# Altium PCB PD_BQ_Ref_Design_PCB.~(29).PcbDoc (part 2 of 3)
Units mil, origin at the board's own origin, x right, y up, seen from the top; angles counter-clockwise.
Board outline 2000 x 3400 mil, 4 copper layers (Top Layer, Signal Layer 1, Signal Layer 2, Bottom Layer), stack 61.2 mil thick; 124 components, 53 nets, 359 pads, 494 vias.
Unrouted connection lines stored in the file: 227.

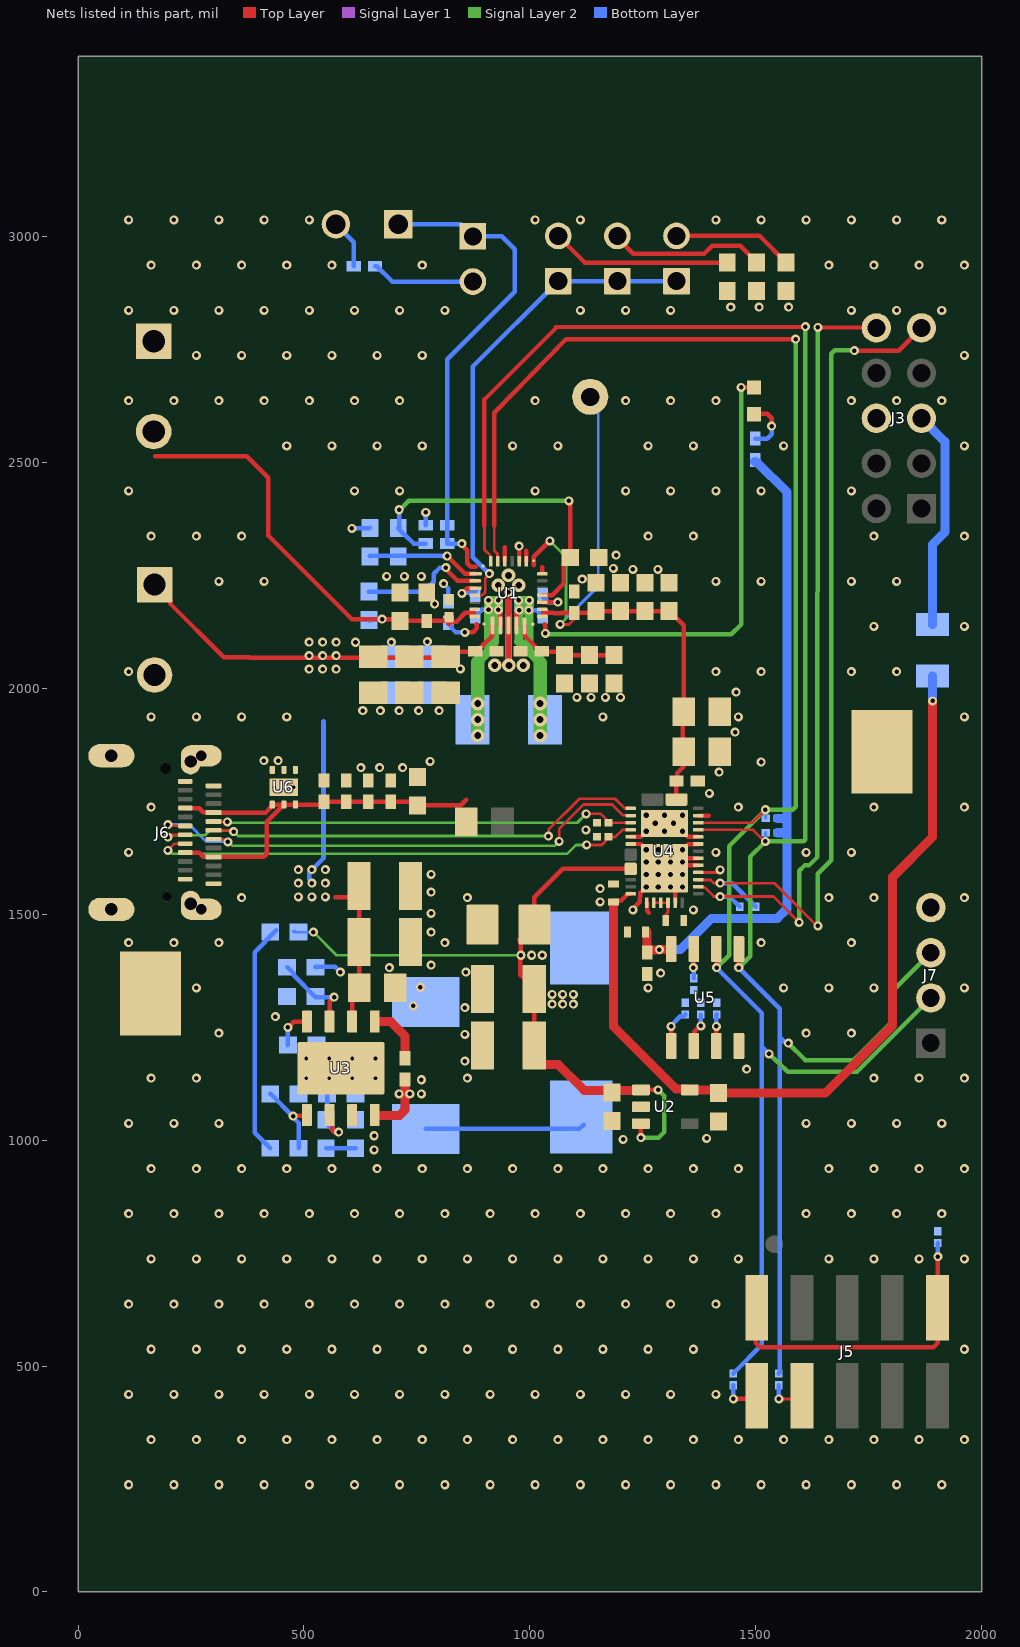
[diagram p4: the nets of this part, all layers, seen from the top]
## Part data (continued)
LOGO5: library part CMP-0074837-1, "IEC 61010-1 Hot Surface Warning"
NT1: library part CMP-0078142-3, "Single point connection between nets.", Manufacturer=N/A
R1: library part CMP-0022736-4, "RES, 100, 1%, 0.1 W, 0603", Manufacturer=Yageo, Power_W=100mW, Supplier Part Number 1=311-100HRCT-ND, TempCo="100 ppm/C", Tolerance_%=1%, Value2=0.1W, Value_Code=100R, ValueDisplayed=100
R2: library part CMP-0026232-2, "RES, 2.21 k, 1%, 0.063 W, AEC-Q200 Grade 0, 0402", Manufacturer=Vishay-Dale, Power_W=63mW, Supplier Part Number 1=541-2.21KLCT-ND, TempCo="100 ppm/C", Tolerance_%=1%, Value2=0.063W, Value_Code=2k21, ValueDisplayed=2.21k
R3: library part CMP-0026464-2, "RES, 5.23 k, 1%, 0.063 W, AEC-Q200 Grade 0, 0402", Manufacturer=Vishay-Dale, PartNumber=CRCW04025K23FKED, Power_W=63mW, Supplier Part Number 1=541-5.23KLCT-ND, TempCo="100 ppm/C", Tolerance_%=1%, Value2=0.063W, Value_Code=5k23, ValueDisplayed=5.23k
R4: library part CMP-0022788-4, "RES, 137 k, 1%, 0.1 W, 0603", Manufacturer=Yageo, Power_W=100mW, Supplier Part Number 1=311-137KHRCT-ND, TempCo="100 ppm/C", Tolerance_%=1%, Value2=0.1W, Value_Code=137k
R5: library part CMP-0026284-2, "RES, 30.1 k, 1%, 0.063 W, AEC-Q200 Grade 0, 0402", Manufacturer=Vishay-Dale, PartNumber=CRCW040230K1FKED, Power_W=63mW, Supplier Part Number 1=541-30.1KLCT-ND, TempCo="100 ppm/C", Tolerance_%=1%, Value2=0.063W, Value_Code=30k1, ValueDisplayed=30.1k
R6: library part CMP-0022735-5, "RES, 100 k, 1%, 0.1 W, 0603", Manufacturer=Yageo, Power_W=100mW, Supplier Part Number 1=311-100KHRCT-ND, TempCo="100 ppm/C", Tolerance_%=1%, Value2=0.1W, Value_Code=100k
R7: library part CMP-0025958-3, "RES, 10.0 k, 1%, 0.063 W, AEC-Q200 Grade 0, 0402", Manufacturer=Vishay-Dale, PartNumber=CRCW040210K0FKED, Power_W=63mW, Supplier Part Number 1=541-10.0KLCT-ND, TempCo="100 ppm/C", Tolerance_%=1%, Value2=0.063W, Value_Code=10k0, ValueDisplayed=10.0k
R8: library part CMP-0023246-5, "RES, 6.04 k, 1%, 0.1 W, 0603", Manufacturer=Yageo, Power_W=100mW, Supplier Part Number 1=311-6.04KHRCT-ND, TempCo="100 ppm/C", Tolerance_%=1%, Value2=0.1W, Value_Code=6k04, ValueDisplayed=6.04k
R9: library part CMP-0022000-4, "RES, 10.5 k, 1%, 0.1 W, AEC-Q200 Grade 0, 0603", Manufacturer=Vishay-Dale, Power_W=100mW, Supplier Part Number 1=541-10.5KHCT-ND, TempCo="100 ppm/C", Tolerance_%=1%, Value2=0.1W, Value_Code=10k5, ValueDisplayed=10.5k
R10: library part CMP-0022089-4, "RES, 17.4 k, 1%, 0.1 W, AEC-Q200 Grade 0, 0603", Manufacturer=Vishay-Dale, Power_W=100mW, Supplier Part Number 1=541-17.4KHCT-ND, TempCo="100 ppm/C", Tolerance_%=1%, Value2=0.1W, Value_Code=17k4, ValueDisplayed=17.4k
R11: library part CMP-0017299-3, "RES, 10.0, 1%, 0.25 W, AEC-Q200 Grade 0, 1206", Manufacturer=Panasonic, Power_W=250mW, Supplier Part Number 1=P10.0FCT-ND, TempCo="100 ppm/C", Tolerance_%=1%, Value2=0.25W, Value_Code=10R0, ValueDisplayed=10.0
R12: library part CMP-0022483-4, "RES, 51.1, 1%, 0.1 W, AEC-Q200 Grade 0, 0603", Manufacturer=Vishay-Dale, Power_W=100mW, Supplier Part Number 1=541-51.1HCT-ND, TempCo="100 ppm/C", Tolerance_%=1%, Value2=0.1W, Value_Code=51R1, ValueDisplayed=51.1
R13: library part CMP-0022546-4, "RES, 665 k, 1%, 0.1 W, AEC-Q200 Grade 0, 0603", Manufacturer=Vishay-Dale, Power_W=100mW, Supplier Part Number 1=541-665KHCT-ND, TempCo="100 ppm/C", Tolerance_%=1%, Value2=0.1W, Value_Code=665k
R14: library part CMP-0021999-4, "RES, 10.2 k, 1%, 0.1 W, AEC-Q200 Grade 0, 0603", Manufacturer=Vishay-Dale, Power_W=100mW, Supplier Part Number 1=541-10.2KHCT-ND, TempCo="100 ppm/C", Tolerance_%=1%, Value2=0.1W, Value_Code=10k2, ValueDisplayed=10.2k
R15: library part CMP-0022036-4, "RES, 130 k, 1%, 0.1 W, AEC-Q200 Grade 0, 0603", Manufacturer=Vishay-Dale, Power_W=100mW, Supplier Part Number 1=541-130KHCT-ND, TempCo="100 ppm/C", Tolerance_%=1%, Value2=0.1W, Value_Code=130k
R16: library part CMP-0022137-4, "RES, 1.96 k, 1%, 0.1 W, AEC-Q200 Grade 0, 0603", Manufacturer=Vishay-Dale, Power_W=100mW, Supplier Part Number 1=541-1.96KHCT-ND, TempCo="100 ppm/C", Tolerance_%=1%, Value2=0.1W, Value_Code=1k96, ValueDisplayed=1.96k
R17: library part CMP-0022360-4, "RES, 37.4 k, 1%, 0.1 W, AEC-Q200 Grade 0, 0603", Manufacturer=Vishay-Dale, Power_W=100mW, Supplier Part Number 1=541-37.4KHCT-ND, TempCo="100 ppm/C", Tolerance_%=1%, Value2=0.1W, Value_Code=37k4, ValueDisplayed=37.4k
R21 R22 R24 R25: library part CMP-0027272-3, "RES, 2.20 k, 1%, 0.05 W, 0201", Manufacturer=Vishay-Dale, Power_W=50mW, Supplier Part Number 1=541-2.20KAABCT-ND, TempCo="100 ppm/C", Tolerance_%=1%, Value2=0.05W, Value_Code=2k20, ValueDisplayed=2.20k
R26 R27 R29: library part CMP-0027008-4, "RES, 0, 5%, 0.05 W, 0201", Manufacturer=Vishay-Dale, Power_W=50mW, Supplier Part Number 1=72M6743, TempCo=ppm/C, Tolerance_%=5%, Value2=0.05W, Value_Code=0000, ValueDisplayed=0
R28 R30 R31 R32: library part CMP-0027262-3, "RES, 10.0 k, 1%, 0.05 W, 0201", Manufacturer=Vishay-Dale, Power_W=50mW, Supplier Part Number 1=541-10.0KAABCT-ND, TempCo="100 ppm/C", Tolerance_%=1%, Value2=0.05W, Value_Code=10k0, ValueDisplayed=10.0k
SH-J1 SH-J2: library part CMP-0003623-1, "Shunt, 100mil, Gold plated, Black", Alternate Manufacturer=3M, Alternate PartNumber=969102-0000-DA, Manufacturer=Samtec, Supplier Part Number 1=SNT-100-BK-G-ND
TP1: library part CMP-0055137-1, "Test Point, Miniature, Red, TH", Color=Red, Manufacturer=Keystone, Supplier Part Number 1=36-5000-ND
TP2 TP3: library part CMP-0055153-1, "Test Point, Compact, SMT", Manufacturer=Keystone, Supplier Part Number 1=36-5016TR-ND
U1: library part CMP-0088656-1, "BQ2579x HotRod", Manufacturer="Texas Instruments", Operating Temperature Range=to
U2: library part CMP-0074640-3, "500-mA, Low IQ, Small Size, Low Dropout Regulator, DBV0005A (SOT-23-5)", Alternate Manufacturer="Texas Instruments"
U3: library part CMP-0067056-2, "3.5V to 28V Input, 5A, 570kHz Step-Down Converter with Eco-mode, DDA0008E (SOIC-8)", Alternate Manufacturer="Texas Instruments", Alternate PartNumber=TPS54531DDA
U4: library part CMP-0090338-5, "USB Type-C and USB PD Controller with Integrated Power Switches Optimized for Power Applications", Manufacturer="Texas Instruments", Max Supply Voltage=22V, Min Supply Voltage=3V, Operating Temperature Range="-40°C to +125°C"
U5: library part CMP-0005314-2, "256 kb I2C CMOS Serial EEPROM, SOIC-8", Manufacturer="ON Semiconductor", Supplier Part Number 1=CAT24C256WI-G-ND
U6: library part CMP-0077834-1, "22-V Precision Surge Protection Clamp, DRV0006A (WSON-6)", Alternate Manufacturer="Texas Instruments"
ZZ1: library part CMP-0003616-3

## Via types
v1: diameter 20, hole 10, Top Layer to Bottom Layer, tented both sides, 445 vias
v2: diameter 23.62, hole 11.81, Top Layer to Bottom Layer, 24 vias
v3: diameter 30, hole 15, Top Layer to Bottom Layer, tented both sides, 12 vias
v4: diameter 19.68, hole 7.87, Top Layer to Bottom Layer, tented both sides, 10 vias
v5: diameter 20, hole 10, Top Layer to Bottom Layer, 3 vias

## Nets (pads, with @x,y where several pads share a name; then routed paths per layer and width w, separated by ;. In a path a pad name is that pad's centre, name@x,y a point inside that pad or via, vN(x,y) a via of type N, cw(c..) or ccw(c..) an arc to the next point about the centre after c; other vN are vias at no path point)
AGND: C22.2 J3.6 J4.2 NT1.2 R5.1 R6.1 R7.1 R8.1 R9.1 R10.1 U1.10 U1.11 U1.13 | length 298.5
  Top Layer w10: 944.88,2312.99 945,2312.87 U1.13@945,2281.4 ; 976.38,2303.15 976.38,2281.51 U1.11@976.5,2281.4 ; 992.13,2305.12 992.24,2305 U1.10@992.24,2281.4
  Bottom Layer w10: J4.2@570.87,3027.56 610.24,2988.19 R7.1@610.24,2935.04 ; v1(606.3,2354.33) 644.87,2354.33 R6.1@645.85,2355.32 ; v1(769.69,2389.76) 769.69,2361.34 R5.1@769.8,2361.22 ; v1(809.06,2232.28) 820,2221.34 C22.2@820,2192.91
  other v1: 976.38,2314.96 1444.88,2844.49 1507.87,2844.49 1572.83,2844.49
BAT: C19.1 C20.1 C21.1 J2.2 R1.1 U1.22 U1.23 | length 977.6
  Top Layer w10: 171.26,2514.17 373.62,2514.17 421.26,2466.54 421.26,2338.58 606.3,2153.54 v1(672.86,2153.54) 708.78,2153.54 C21.1@712.72,2149.61 C20.1@771.77,2149.61 815.08,2149.61 820.98,2143.7 ; 820.98,2141.73 820.98,2143.7 ; 877.09,2167.32 857.4,2167.32 837.83,2147.75 825.04,2147.75 820.98,2143.7
  Bottom Layer w10: R1.1@643.7,2151.57 645.67,2149.61 649.61,2153.54 v1(672.86,2153.54)
C_CC1: C42.1 J6.A5 U4.28 | length 942.2
  Top Layer w6: J6.A5@300.2,1705.71 300.69,1705.22 330.22,1705.22 v1(330.71,1704.72) ; v1(1124.81,1722.44) 1157.38,1722.44 1174.41,1705.41 C42.1@1174.41,1702.76 1223.06,1702.76 U4.28@1223.24,1702.94
  Signal Layer 2 w6: v1(330.71,1704.72) 332.68,1702.76 1105.12,1702.76 v1(1124.81,1722.44)
C_CC2: C41.1 J6.B5 U4.29 | length 1095.8
  Top Layer w6: v1(198.82,1641.73) 213.58,1656.5 J6.B5@237.2,1656.5 ; v1(1125.98,1653.54) 1159.35,1653.54 1174.41,1668.61 C41.1@1174.41,1671.26 1188.98,1671.26 1204.91,1687.19 U4.29@1223.24,1687.19
  Signal Layer 2 w6: v1(198.82,1641.73) 201.46,1641.73 209.33,1633.86 1082.68,1633.86 1102.36,1653.54 v1(1125.98,1653.54)
C_USB_N: J6.A7 J6.B7 U4.27 | length 1182
  Top Layer w6: v1(198.82,1698.82) 201.77,1695.87 J6.B7@237.2,1695.87 ; J6.A7@300.2,1666.34 325.79,1666.34 v1(331.63,1660.49) ; v1(1064.96,1661.42) 1064.96,1688.98 1118.92,1742.94 1182.26,1742.94 1205.57,1719.62 1222.3,1719.62 U4.27@1223.24,1718.68
  Signal Layer 2 w6: v1(331.63,1660.49) 333.23,1660.49 342.15,1651.57 1054.45,1651.57 v1@1064.62,1661.75
  Bottom Layer w6: v1(198.82,1698.82) 246.06,1698.82 284.39,1660.49 v1(331.63,1660.49) ; v1@1064.29,1661.42 v1(1064.96,1661.42)
C_USB_P: J6.A6 J6.B6 U4.26 | length 1175.4
  Top Layer w6: v1(198.82,1670.82) 202.61,1670.82 207.97,1676.18 J6.B6@237.2,1676.18 ; J6.A6@300.2,1686.02 337.75,1686.02 340.7,1683.07 v1(344.49,1683.07) ; v1(1041.34,1673.23) 1041.88,1673.77 1041.88,1687.55 1110.24,1755.91 1188.98,1755.91 1209.51,1735.37 1222.3,1735.37 U4.26@1223.24,1734.43
  Signal Layer 2 w6: v1(198.82,1670.82) 202.61,1670.82 206.99,1675.2 281.5,1675.2 292.32,1686.02 333.97,1686.02 334.25,1685.75 341.81,1685.75 v1(344.49,1683.07) ; v1@343.01,1684.55 354.33,1673.23 v1(1041.34,1673.23)
GND: C2.1 C3.1 C4.1 C5.1 C6.2 C8.1 C9.1 C10.1 C11.2 C12.2 C13.2 C14.2 C15.2 C16.2 C17.2 C18.2 C19.2 C20.2 C21.2 C23.1 C24.1 C26.2 C27.2 C28.2 C29.2 C30.2 C31.2 C33.2 C34.2 C35.2 C36.2 C37.2 C38.2 C39.2 C40.2 C41.2 C42.2 C43.2 C44.2 C45.1 C46.1 C47.1 C48.1 D2.2 J1.2 J2.1 J6.A1 J6.A12 J6.B1 J6.B12 J6.S1 J6.S2 J6.S3 J6.S4 J7.4 NT1.1 R15.1 R16.1 R17.1 R28.1 R29.1 R30.1 R31.1 R32.1 TP2.1 TP3.1 U1.27 U2.2 U3.7 U3.9@581.69,1159.17 U4.5 U4.10 U4.11 U4.12 U4.14 U4.18 U4.31 U4.39 U5.4 U6.1 U6.2 U6.3 U6.7@455.71,1781.5 | length 894.8
  Top Layer w6: U4.10@1372.84,1592.7 1415.54,1592.7 v1(1421.26,1598.43)
  Top Layer w8: U4.31@1223.24,1655.69 1245.68,1655.69
  Top Layer w10: 952.87,2167.32 U1.27@952.87,2139.66 952.87,2051.18 v3(953.86,2051.18) ; v1(1228.35,1509.84) 1228.35,1512.55 1243.67,1527.87 1243.67,1537.15 1245.05,1538.53 1245.05,1547.58 1298.04,1600.57 U4.39@1298.04,1601.95 ; 1245.68,1655.69 U4.39@1298.04,1603.33 ; U4.39@1311.62,1588.37 U4.39@1298.04,1601.95 ; U4.39@1311.62,1615.54 U4.39@1298.04,1601.95 ; U4.39@1319.59,1624.89 1350.4,1655.69 U4.14@1372.84,1655.69 ; U4.39@1320.28,1624.2 U4.12@1372.84,1624.2 U4.39@1338.2,1624.2 ; U4.5@1321.66,1525.77 U4.39@1321.66,1578.33 ; U4.39@1338.2,1608.45 U4.11@1372.84,1608.45 ; U4.18@1372.84,1718.68 1395.85,1718.68
  Top Layer w15: 952.87,2167.32 v1@952.87,2212.79
  Signal Layer 1 w15: v1(952.87,2212.81) 952.99,2212.69 952.99,2052.05 v3(953.86,2051.18)
  other v1: 111.94,237.26 211.94,237.26 311.94,237.26 411.94,237.26 511.94,237.26 611.94,237.26 711.94,237.26 811.94,237.26 911.94,237.26 1011.94,237.26 1111.94,237.26 1211.94,237.26 1311.94,237.26 1411.94,237.26 1511.94,237.26 1611.94,237.26 1711.94,237.26 1811.94,237.26 1911.94,237.26 161.94,337.26 261.94,337.26 361.94,337.26 461.94,337.26 561.94,337.26 661.94,337.26 761.94,337.26 861.94,337.26 961.94,337.26 1061.94,337.26 1161.94,337.26 1261.94,337.26 1361.94,337.26 1461.94,337.26 1561.94,337.26 1661.94,337.26 1761.94,337.26 1861.94,337.26 1961.94,337.26 111.94,437.26 211.94,437.26 311.94,437.26 411.94,437.26 511.94,437.26 611.94,437.26 711.94,437.26 811.94,437.26 911.94,437.26 1011.94,437.26 1111.94,437.26 1211.94,437.26 1311.94,437.26 1411.94,437.26 161.94,537.26 261.94,537.26 361.94,537.26 461.94,537.26 561.94,537.26 661.94,537.26 761.94,537.26 861.94,537.26 961.94,537.26 1061.94,537.26 1161.94,537.26 1261.94,537.26 1361.94,537.26 1961.94,537.26 111.94,637.26 211.94,637.26 311.94,637.26 411.94,637.26 511.94,637.26 611.94,637.26 711.94,637.26 811.94,637.26 911.94,637.26 1011.94,637.26 1111.94,637.26 1211.94,637.26 1311.94,637.26 1411.94,637.26 161.94,737.26 261.94,737.26 361.94,737.26 461.94,737.26 561.94,737.26 661.94,737.26 761.94,737.26 861.94,737.26 961.94,737.26 1061.94,737.26 1161.94,737.26 1261.94,737.26 1361.94,737.26 1461.94,737.26 1661.94,737.26 1761.94,737.26 1861.94,737.26 1961.94,737.26 111.94,837.26 211.94,837.26 311.94,837.26 411.94,837.26 511.94,837.26 611.94,837.26 711.94,837.26 811.94,837.26 911.94,837.26 1011.94,837.26 1111.94,837.26 1211.94,837.26 1311.94,837.26 1411.94,837.26 1611.94,837.26 1711.94,837.26 1811.94,837.26 1911.94,837.26 161.94,937.26 261.94,937.26 361.94,937.26 461.94,937.26 561.94,937.26 661.94,937.26 761.94,937.26 861.94,937.26 961.94,937.26 1061.94,937.26 1161.94,937.26 1261.94,937.26 1361.94,937.26 1461.94,937.26 1661.94,937.26 1761.94,937.26 1861.94,937.26 1961.94,937.26 655.51,978.35 1206.69,1001.97 1391.42,1003.94 655.51,1009.84 111.94,1037.26 211.94,1037.26 311.94,1037.26 1611.94,1037.26 1711.94,1037.26 1811.94,1037.26 1911.94,1037.26 161.94,1137.26 261.94,1137.26 861.94,1137.26 1761.94,1137.26 1861.94,1137.26 1961.94,1137.26 1480,1157.48 856.3,1175.2 856.3,1234.25 311.94,1237.26 1611.94,1237.26 1711.94,1237.26 437.01,1273.62 856.3,1293.31 742.13,1297.24 261.94,1337.26 1261.94,1337.26 1561.94,1337.26 1661.94,1337.26 1761.94,1337.26 1961.94,1337.26 757.87,1338.58 1289.37,1370.08 858.27,1372.05 688.98,1381.89 781.5,1387.8 111.94,1437.26 211.94,1437.26 311.94,1437.26 811.94,1437.26 1511.94,1437.26 1711.94,1437.26 781.5,1460.63 781.5,1501.97 1362.2,1509.84 1155.51,1527.56 361.94,1537.26 861.94,1537.26 1661.94,1537.26 1761.94,1537.26 1961.94,1537.26 781.5,1549.21 1155.51,1557.09 781.5,1588.58 111.94,1637.26 1411.94,1637.26 1611.94,1637.26 1711.94,1637.26 1124.02,1687.01 161.94,1737.26 1461.94,1737.26 1761.94,1737.26 1961.94,1737.26 1397.64,1767.72 1419.29,1814.96 625.98,1824.8 667.32,1824.8 718.5,1824.8 1511.94,1837.26 779.53,1838.58 411.42,1840.55 442.91,1840.55 1454.72,1903.54 161.94,1937.26 261.94,1937.26 361.94,1937.26 461.94,1937.26 1161.94,1937.26 1461.94,1937.26 1961.94,1937.26 630.2,1950.78 669.29,1950.79 710.63,1950.79 753.94,1950.79 799.21,1950.79 1104.33,1980.32 1135.83,1980.32 1167.32,1980.32 1200.79,1980.32 1456.69,1992.13 111.94,2037.26 1411.94,2037.26 1511.94,2037.26 1711.94,2037.26 1811.94,2037.26 1761.94,2137.26 1961.94,2137.26 789.37,2187.01 311.94,2237.26 411.94,2237.26 1411.94,2237.26 1511.94,2237.26 1711.94,2237.26 1811.94,2237.26 1116.14,2242.13 683.07,2248.03 722.44,2248.03 759.84,2248.03 1228.35,2263.78 1283.46,2263.78 1185.04,2265.75 1190.94,2295.28 161.94,2337.26 261.94,2337.26 361.94,2337.26 1261.94,2337.26 1361.94,2337.26 1761.94,2337.26 1961.94,2337.26 111.94,2437.26 611.94,2437.26 711.94,2437.26 1011.94,2437.26 1211.94,2437.26 1311.94,2437.26 1411.94,2437.26 1511.94,2437.26 1711.94,2437.26 461.94,2537.26 561.94,2537.26 661.94,2537.26 761.94,2537.26 961.94,2537.26 1061.94,2537.26 1261.94,2537.26 1361.94,2537.26 1561.94,2537.26 1961.94,2537.26 111.94,2637.26 211.94,2637.26 311.94,2637.26 411.94,2637.26 511.94,2637.26 611.94,2637.26 711.94,2637.26 1011.94,2637.26 1211.94,2637.26 1311.94,2637.26 1411.94,2637.26 1711.94,2637.26 1811.94,2637.26 1911.94,2637.26 261.94,2737.26 361.94,2737.26 461.94,2737.26 561.94,2737.26 661.94,2737.26 761.94,2737.26 1961.94,2737.26 111.94,2837.26 211.94,2837.26 311.94,2837.26 411.94,2837.26 511.94,2837.26 611.94,2837.26 711.94,2837.26 811.94,2837.26 1111.94,2837.26 1211.94,2837.26 1311.94,2837.26 1711.94,2837.26 1811.94,2837.26 1911.94,2837.26 161.94,2937.26 261.94,2937.26 361.94,2937.26 461.94,2937.26 561.94,2937.26 761.94,2937.26 1661.94,2937.26 1761.94,2937.26 1861.94,2937.26 1961.94,2937.26 111.94,3037.26 211.94,3037.26 311.94,3037.26 411.94,3037.26 511.94,3037.26 1011.94,3037.26 1111.94,3037.26 1411.94,3037.26 1511.94,3037.26 1611.94,3037.26 1711.94,3037.26 1811.94,3037.26 1911.94,3037.26
  other v2: 1257.88,1560.61 1284.65,1560.61 1311.43,1560.61 1338.2,1560.61 1257.88,1588.17 1284.65,1588.17 1311.43,1588.17 1338.2,1588.17 1257.88,1615.73 1284.65,1615.73 1311.43,1615.73 1338.2,1615.73 1257.88,1643.29 1284.65,1643.29 1311.43,1643.29 1338.2,1643.29
  other v3: 922.36,2051.18 985.35,2051.18 930.22,2228.33 975.51,2228.35 952.86,2250.2
  other v4: 504.92,1137.52 556.1,1137.52 607.28,1137.52 658.46,1137.52 504.92,1180.83 556.1,1180.83 607.28,1180.83 658.46,1180.83 434.06,1781.5 477.36,1781.5
I2C1_SCL: J3.9 R21.1 U4.9 | length 1911.4
  Top Layer w6: U4.9@1372.84,1576.95 1373.78,1576.02 1400.47,1576.02 1407.59,1568.9 v1(1421.26,1568.9) 1541.34,1568.9 1636.81,1473.43 v5@1637.8,1472.44
  Top Layer w10: v5(1718.5,2748.03) 1816.93,2748.03 J3.9@1867.13,2798.23
  Signal Layer 2 w10: v5(1637.8,1474.41) 1637.8,1590.14 1667.32,1619.67 1667.32,2740.91 1675.2,2748.78 1717.76,2748.78 v5(1718.5,2748.03)
  Bottom Layer w10: v1(1421.26,1568.9) 1448.03,1568.9 R21.1@1500,1516.93
I2C1_SDA: J3.10 R22.1 U4.8 | length 1783.2
  Top Layer w6: U4.8@1372.84,1561.2 1373.78,1560.27 1386.58,1560.27 1407.48,1539.37 v1(1421.26,1539.37) 1539.37,1539.37 v1(1596.46,1482.28) v1@1596.46,1480.32
  Top Layer w10: v5(1637.8,2799.21) J3.10@1767.13,2798.23
  Signal Layer 2 w10: v1(1596.46,1482.28) 1596.46,1596.46 1608.27,1608.27 1618.11,1608.27 1635.83,1625.98 1637.8,2801.18 v5(1637.8,2799.21)
  Bottom Layer w10: v1(1421.26,1539.37) 1442.13,1539.37 R22.1@1464.57,1516.93
I2C_SCL: J7.2 R24.2 R26.1 U1.14 U4.17 U5.6 | length 4218
  Top Layer w6: 921.26,2360.24 921.26,2305.12 928.31,2298.06 928.31,2282.33 U1.14@929.25,2281.4 ; U4.17@1372.84,1702.94 1493.06,1702.94 v1(1521.65,1731.53)
  Top Layer w10: 921.26,2360.24 921.26,2610.24 1080.71,2773.62 v1(1588.58,2773.62) ; v1(1413.39,1381.89) U5.6@1413.39,1422.76
  Signal Layer 2 w10: v1(1413.39,1381.89) 1441.26,1409.76 1441.26,1651.14 v1(1521.65,1731.53) 1581.93,1731.53 1588.58,1738.19 v1(1588.58,2773.62) ; v1(1529.53,1190.94) 1570.87,1151.57 1724.41,1151.57 J7.2@1887.8,1314.96
  Bottom Layer w6: v1(1521.65,1731.53) 1521.65,1713.39 R24.2@1522.44,1712.6
  Bottom Layer w10: v1(1413.39,1381.89) 1513.78,1281.5 1513.78,1204.72 ; R26.1@1450.79,483.46 1450.79,484.25 1454.06,487.52 1454.14,487.52 1513.78,547.16 1513.78,1204.72 ; v1(1529.53,1190.94) 1515.75,1204.72 1513.78,1204.72
I2C_SDA: J7.3 R25.2 R27.1 U1.15 U4.16 U5.5 | length 4321.3
  Top Layer w6: 899.61,2360.24 899.61,2307.09 912.57,2294.13 912.57,2282.33 U1.15@913.5,2281.4 ; U4.16@1372.84,1687.19 1493.91,1687.19 1519.69,1661.42 v1(1521.65,1661.42)
  Top Layer w10: 899.61,2360.24 899.61,2639.76 1059.06,2799.21 ; 1057.09,2799.21 v1@1608.27,2801.18 ; v1(1462.6,1381.89) U5.5@1462.6,1422.76
  Signal Layer 2 w10: v1(1462.6,1381.89) 1488.19,1407.48 1488.19,1627.95 v1(1521.65,1661.42) 1606.3,1661.42 1610.24,1665.35 v1(1610.24,2801.18) ; v1(1572.44,1214.96) 1610.24,1177.17 1716.54,1177.17 1801.18,1261.81 1801.18,1328.35 J7.3@1887.8,1414.96
  Bottom Layer w6: v1(1521.65,1661.42) 1521.65,1680.31 R25.2@1522.44,1681.1
  Bottom Layer w10: v1(1462.6,1381.89) 1553.15,1291.34 1553.15,1228.35 ; R27.1@1551.18,483.46 1553.15,485.43 1553.15,1228.35 ; v1(1572.44,1214.96) 1566.54,1214.96 1553.15,1228.35
ILIM_HIZ: R4.1 R6.2 U1.17 | length 250.9
  Top Layer w10: v1(816.93,2293.3) 856.39,2253.84 U1.17@880.04,2253.84
  Bottom Layer w10: R6.2@645.85,2292.32 646.84,2293.31 806.61,2293.31 v1(816.93,2293.3)
LDO_1V5: C37.1 U4.2 U4.3 U4.4 | length 83
  Top Layer w6: U4.2@1274.42,1525.77 U4.3@1290.17,1525.77 U4.4@1305.91,1525.77 1305.91,1504.73 1301.18,1500 1301.18,1476.69 C37.1@1300.87,1476.38
LDO_3V3: C36.1 C43.1 R2.2 R21.2 R22.2 R24.1 R25.1 U4.1 U5.8 | length 1507.2
  Top Layer w10: U4.1@1258.67,1525.77 1259.73,1524.71 1259.73,1507.98 1263.78,1503.94
  Top Layer w20: C43.1@1259.84,1415.35 1259.84,1419.29 C43.1@1261.65,1421.1 ; C36.1@1259.84,1461.46 1259.84,1421.1 C43.1@1261.65,1421.1 ; U5.8@1312.99,1423.15 1311.73,1421.89 v1(1286.7,1421.89) 1286.07,1421.26 1273.37,1421.26 1273.21,1421.1 C43.1@1261.65,1421.1
  Bottom Layer w20: v1@1287.4,1421.89 1333.31,1421.89 1402.36,1490.95 1472.44,1490.95 1501.97,1490.95 1531.5,1490.95 1548.03,1490.95 1568.9,1511.81 1568.9,1680.61 ; R2.2@1498.03,2502.95 1500.83,2500.16 1503.78,2500.16 1568.9,2435.04 1568.9,1713.17 ; R25.1@1548.43,1681.1 1548.92,1680.61 1568.9,1680.61 ; R24.1@1548.43,1712.6 1568.32,1712.6 1568.9,1713.17 ; 1568.9,1680.61 1568.9,1713.17
NetC1_1: C1.1 U1.4 | length 76.9
  Top Layer w10: U1.4@1027.68,2190.84 1062.03,2190.84 v1(1062.13,2190.95)
  Bottom Layer w10: C1.1@1028.66,2206.69 1028.66,2202.76 1040.57,2190.84 1062.03,2190.84 v1(1062.13,2190.95)
NetC1_2: C1.2 L1.1 U1.28 | length 640.5
  Top Layer w10: U1.28@970.59,2139.66 971.65,2140.73 971.65,2168.5 v1(976.38,2173.23)
  Signal Layer 2 w20: 1022.76,2057.09 998.36,2081.48 ; v1(976.38,2173.23) 976.38,2194.02 v1(975.51,2194.88) v1(999.13,2194.88) 998.03,2193.78 v1(998.03,2173.23) ; v1(976.38,2173.23) v1(998.03,2173.23) ; v1(976.38,2173.23) 976.38,2105.23 975.49,2104.35 998.36,2081.48 ; v1(998.03,2173.23) 998.36,2172.9 998.36,2081.48
  Signal Layer 2 w30: v3(1022.76,1895.67) 1022.76,2057.09
  Bottom Layer w10: v1(998.03,2173.23) 1014.88,2173.23 C1.2@1028.66,2159.45
  Bottom Layer w20: v1@975.51,2175 976.38,2174.13 v1(976.38,2173.23) v1(998.03,2173.23) 998.03,2193.78 v1(999.13,2194.88) v1(975.51,2194.88) v1@975.51,2175
  other v3: 1022.76,1931.1 1022.76,1966.7
NetC7_1: C7.1 U1.19 | length 77
  Top Layer w10: v1(849.53,2210.63) 861.24,2222.34 U1.19@879.65,2222.34
  Bottom Layer w10: v1(849.53,2210.63) 851.03,2212.13 873.61,2212.13 C7.1@879.05,2206.69 ; C7.1@874.29,2210.63 C7.1@881.1,2217.44
NetC7_2: C7.2 L1.2 U1.26 | length 624.4
  Top Layer w10: v1(930.24,2173.8) 930.24,2172.49 934.09,2168.63 934.09,2140.73 U1.26@935.16,2139.66
  Signal Layer 2 w20: 884.96,2058.3 908.58,2081.93 v1(908.58,2174.62) 929.41,2174.62 v1(930.24,2173.8) ; 908.58,2088.58 922.36,2102.36 922.36,2165.92 v1(930.24,2173.8) ; v1@908.58,2175.61 v1(908.58,2194.88) v1(930.24,2194.88) v1(930.24,2173.8)
  Signal Layer 2 w30: v3(884.96,1895.67) v3(884.96,1931.1) v3(884.96,1966.56) 884.96,2058.3
  Bottom Layer w10: C7.2@879.05,2159.45 894.8,2175.2 895.38,2174.62 v1(908.58,2174.62)
  Bottom Layer w20: v1(908.58,2174.62) 929.41,2174.62 v1(930.24,2173.8) v1(930.24,2194.88) v1(908.58,2194.88) v1(908.58,2174.62)
NetC22_1: C22.1 U1.24 | length 87.7
  Top Layer w10: v1(856.3,2124.02) 856.95,2124.66 874.66,2124.66 882.84,2132.84 882.84,2140.78 881.89,2141.73
  Bottom Layer w10: C22.1@820,2145.67 826.81,2138.86 826.81,2133.81 836.61,2124.02 v1(856.3,2124.02)
NetC25_1: C25.1 U3.1 | length 129.4
  Top Layer w20: U3.1@656.69,1262.52 692.2,1262.52 723.68,1231.04 C25.1@723.68,1181.64
NetC25_2: C25.2 D2.1 L2.1 U3.8 | length 493.1
  Top Layer w20: U3.8@656.69,1055.83 656.81,1055.83 657.52,1055.12 711.96,1055.12 723.68,1066.83 C25.2@723.68,1134.4
  Bottom Layer w10: D2.1@769.69,1024.86 1109.51,1024.86 L2.1@1119.09,1034.45
  other v1: 710.63,1102.36 734.25,1102.36 759.84,1102.36 759.84,1133.86
NetC32_1: C32.1 C34.1 U3.6 | length 164.6
  Top Layer w10: U3.6@556.69,1055.83 562.52,1050 562.52,1022.13 566.93,1017.72 v1(576.77,1017.72)
  Bottom Layer w10: C32.1@550.72,1045.28 C32.1@550.72,1043.82 ; C34.1@551.18,1102.36 551.18,1047.24 C32.1@549.21,1045.28 C32.1@550.72,1043.82 ; C32.1@551.92,1035.66 553.44,1041.19 C32.1@550.72,1043.82 ; v1(576.77,1017.72) 569,1017.72 550.72,1036 C32.1@550.72,1043.82
NetC32_2: C32.2 R17.2 | length 65.9
  Bottom Layer w10: C32.2@549.21,982.28 R17.2@615.16,982.28
NetC33_1: C33.1 U3.4 | length 86.7
  Top Layer w10: v1(464.57,1250) 477.09,1262.52 U3.4@506.69,1262.52
  Bottom Layer w10: C33.1@464.57,1210.63 v1(464.57,1250)
NetC44_1: C44.1 C45.2 C46.2 C47.2 C48.2 J6.A4 J6.A9 J6.B4 J6.B9 L3.1 U6.4 U6.5 U6.6 | length 961.1
  Top Layer w10: J6.B4@237.2,1636.81 267.95,1636.81 277.48,1627.28 299.88,1627.28 J6.A9@300.2,1626.97 315.32,1626.97 411.46,1626.97 417.32,1632.83 417.32,1704.72 451.85,1739.25 454.8,1739.25 455.71,1740.16 U6.5@455.71,1743.11 ; J6.B9@237.2,1735.24 267.95,1735.24 277.48,1725.71 299.88,1725.71 J6.A4@300.2,1725.39 415.35,1725.39 430.12,1740.16 U6.4@430.12,1743.11 451.85,1743.11 U6.5@455.71,1743.11 ; 859.61,1753.94 846.81,1741.14 C44.1@750.98,1741.14 743.11,1749.02 C48.2@691.93,1749.02 C47.2@642.72,1749.02 C46.2@593.5,1749.02 C45.2@544.29,1749.02 538.39,1743.11 U6.6@481.3,1743.11 U6.5@455.71,1743.11
NetD1_1: D1.1 R2.1 | length 119.8
  Top Layer w10: D1.1@1496.06,2607.28 1497.05,2608.27 1525.59,2608.27 1535.43,2598.43 v1(1535.43,2580.71)
  Bottom Layer w10: R2.1@1499.02,2553.15 1525.59,2553.15 1535.43,2562.99 v1(1535.43,2580.71)
NetJ3_5: J3.5 R11.1 | length 489.2
  Bottom Layer w20: J3.5@1867.13,2598.23 1918.94,2546.42 1918.94,2346.1 1891.73,2318.9 R11.1@1891.73,2141.73
NetJ5_1: J5.1 R26.2 | length 85
  Top Layer w10: v1(1450.79,427.17) 1495.61,427.17 J5.1@1502.58,434.13
  Bottom Layer w10: v1(1450.79,427.17) R26.2@1450.79,457.48
NetJ5_2: J5.2 J5.10 R29.2 | length 712.5
  Top Layer w10: J5.2@1502.58,629.01 1500.1,626.53 1500.1,551.09 1509.84,541.34 1893.7,541.34 1903.45,551.09 1903.45,628.14 J5.10@1902.58,629.01 1903.54,629.98 v1(1903.54,742.13)
  Bottom Layer w10: v1(1903.54,742.13) R29.2@1903.54,772.44
NetJ5_3: J5.3 R27.2 | length 84.6
  Top Layer w6: v1(1551.18,427.17) 1595.61,427.17 J5.3@1602.58,434.13
  Bottom Layer w10: v1(1551.18,427.17) R27.2@1551.18,457.48
NetJP1_2: JP1.2 R8.2 | length 398.4
  Top Layer w10: JP1.2@1062.99,3001.77 1121.85,2942.91 R8.2@1437.01,2942.91
NetJP2_2: JP2.2 R9.2 | length 350.8
  Top Layer w10: JP2.2@1193.9,3001.77 1193.9,2997.05 1228.7,2962.24 1385.67,2962.24 1403.74,2980.31 1465.55,2980.31 1501.97,2943.9 R9.2@1501.97,2942.91
NetJP3_2: JP3.2 R10.2 | length 267.1
  Top Layer w10: JP3.2@1324.8,3001.77 1509.05,3001.77 1566.93,2943.9 R10.2@1566.93,2942.91
NetJP4_2: JP4.2 R7.2 | length 230.7
  Bottom Layer w10: R7.2@657.48,2935.04 661.42,2935.04 695.67,2900.79 JP4.2@874.02,2900.79
NetR1_2: R1.2 U1.18 | length 281.9
  Top Layer w10: v1(814.09,2267.72) 814.09,2264.65 839.9,2238.84 878.31,2238.84 U1.18@879.05,2238.09
  Bottom Layer w10: R1.2@643.7,2214.57 765.75,2214.57 787.4,2236.22 787.4,2253.84 787.35,2253.89 801.18,2267.72 v1(814.09,2267.72)
NetR12_1: R12.1 R14.2 | length 516.5
  Bottom Layer w10: R14.2@425.2,982.28 390.75,1016.73 390.75,1416.34 R12.1@438.98,1464.57
NetR13_1: R13.1 R15.2 U3.3 | length 192.6
  Top Layer w10: U3.3@556.69,1262.52 556.69,1306.69 v1(566.93,1316.93)
  Bottom Layer w10: R13.1@462.6,1382.87 463.58,1382.87 477.28,1369.17 477.28,1365.24 524.61,1317.91 R15.2@525.59,1317.91 526.57,1316.93 v1(566.93,1316.93)
NetR14_1: R14.1 R16.2 U3.5 | length 179
  Top Layer w10: v1(475.89,1053.15) 476.76,1054.03 504.89,1054.03 U3.5@506.69,1055.83
  Bottom Layer w10: R16.2@425.2,1102.36 426.18,1102.36 475.39,1053.15 v1(475.89,1053.15) 475.89,1050.44 488.19,1038.14 R14.1@488.19,982.28
NetR28_2: R28.2 U5.C | length 66
  Top Layer w10: v1@1362.6,1382.28 v1(1362.2,1381.89) 1362.2,1422.37 U5.C@1362.99,1423.15
  Bottom Layer w10: v1(1362.2,1381.89) 1362.7,1381.4 1362.7,1358.96 R28.2@1363.19,1358.46
NetR30_2: R30.2 U5.1 | length 87.4
  Top Layer w10: U5.1@1312.99,1208.59 v1(1312.99,1251.97)
  Bottom Layer w10: v1(1312.99,1251.97) 1312.99,1253.94 1333.35,1274.29 1341.22,1274.29 1344.49,1277.56 R30.2@1344.49,1278.35
NetR31_2: R31.2 U5.2 | length 76.5
  Top Layer w10: U5.2@1362.99,1208.59 1364.17,1209.77 1364.17,1240.16 1376.97,1252.95 v1(1378.94,1252.95)
  Bottom Layer w10: v1@1378.44,1253.44 R31.2@1378.44,1277.85
NetR32_2: R32.2 U5.3 | length 69.9
  Top Layer w10: U5.3@1412.99,1208.59 1413.08,1208.68 1413.08,1251.68 v1(1413.17,1251.77)
  Bottom Layer w10: v1(1413.17,1251.77) 1413.28,1251.88 1413.28,1278.24 R32.2@1413.39,1278.35
NetU4_15: U4.15 U4.30 U4.40 | length 233.7
  Top Layer w10: U4.30@1223.24,1671.44 1246.07,1671.44 U4.40@1275.99,1701.36 ; U4.40@1258.08,1683.45 U4.40@1275.99,1701.36 ; U4.15@1372.84,1671.44 1350.01,1671.44 ; U4.40@1275.99,1701.36 v2(1277.96,1701.36) U4.40@1298.04,1701.36 v2(1318.12,1701.36) 1320.09,1701.36 1350.01,1671.44 ; 1350.01,1671.44 1338,1683.45 1350.01,1671.44
  other v2: 1257.88,1683.65 1298.04,1683.65 1338.2,1683.65 1257.88,1719.08 1298.04,1719.08 1338.2,1719.08
P3V3: C24.2 C35.1 R11.2 U2.5 U4.38 | length 1869
  Top Layer w10: C35.1@1185.04,1527.24 1187.54,1529.74 1201.78,1529.74 1217.49,1545.46 U4.38@1223.24,1545.46
  Top Layer w20: C35.1@1185.04,1525.59 1185.04,1251.97 1323.88,1113.13 1352.52,1113.13 U2.5@1354.33,1111.32 ; U2.5@1356.14,1111.32 1410.6,1111.32 C24.2@1417.49,1104.43 1653.64,1104.43 1803.15,1253.94 1803.15,1582.68 1891.73,1671.26 v1(1891.73,1972.44)
  Bottom Layer w20: v1(1891.73,1972.44) R11.2@1891.73,2027.56
PMID: C8.2 C9.2 C10.2 C11.1 U1.29 | length 238.5
  Top Layer w10: U1.29@988.31,2138.68 989.21,2137.77 989.21,2116.22 1015.94,2089.49 1015.94,2087.52 1021.77,2081.69 1069.02,2081.69 C10.2@1076.89,2073.82 C9.2@1132.01,2073.82 C8.2@1186.14,2073.82
PP5V: C23.2 C26.1 C27.1 C28.1 L2.2 R12.2 U2.1 U2.3 U4.34 U4.35 U4.@1223.24,1600.57 | length 1669.2
  Top Layer w10: C28.1@1009.84,1209.65 1010.24,1210.04 1010.24,1334.65 979.25,1365.63 979.25,1408.39 v1(980.31,1409.45) 980.31,1439.57 976.38,1443.5 C26.1@1010.24,1477.36 ; C26.1@1026.97,1460.63 C26.1@1010.24,1477.36 ; U4.@1223.24,1600.57 1073.02,1600.57 1010.24,1537.8 C26.1@1010.24,1477.36 ; v1(1246.06,1005.91) U2.3@1246.06,1036.51 ; U2.1@1246.06,1111.32 1246.23,1111.48 1283.93,1111.48 v1(1284.1,1111.65)
  Top Layer w20: C28.1@1009.84,1209.65 1009.84,1182.91 1025.43,1167.32 1062.99,1167.32 1120.08,1110.24 1177.26,1110.24 C23.2@1182.09,1105.41 1186.91,1110.24 1244.98,1110.24 U2.1@1246.06,1111.32
  Signal Layer 2 w6: v1(520.89,1460.63) 572.08,1409.45 v1(980.31,1409.45)
  Signal Layer 2 w10: v1(1246.06,1005.91) 1285.43,1005.91 1297.24,1017.72 1297.24,1098.43 1284.1,1111.57 v1(1284.1,1111.65)
  Bottom Layer w6: R12.2@476.38,1462.6 478.35,1460.63 480.31,1462.6 482.28,1460.63 v1(520.89,1460.63)
  other v1: 1049.21,1301.18 1072.83,1301.18 1096.46,1301.18 1049.21,1322.83 1072.83,1322.83 1096.46,1322.83 1003.94,1409.45 1027.56,1409.45
PPHV: C2.2 C3.2 C4.2 C5.2 C6.1 C38.1 C39.1 C40.1 TP1.1 U1.2 U1.3 U1.8 U1.9 U4.20 U4.21 U4.22 U4.@1324.67,1754.12 | length 1633.6
  Top Layer w6: 1026.69,2269.69 1027.68,2268.7 ; U1.2@1027.68,2159.35 1027.68,2167.32 U1.3@1027.68,2175.1 ; v1(1066.93,2141.73) 1086.73,2141.73 1105.43,2160.43 C6.1@1098.54,2167.32
  Top Layer w10: 1008.98,2272.67 1008.98,2291.34 ; U1.9@1008.98,2282.87 1008.98,2291.34 ; U1.8@1027.68,2255.91 1027.68,2268.7 ; 1030.63,2167.32 1053.53,2167.32 1053.84,2167.01 1070.41,2167.01 1070.72,2167.32 C6.1@1098.54,2167.32 1142.83,2167.32 C5.2@1146.77,2171.26 C4.2@1200.91,2171.26 C3.2@1255.04,2171.26 1309.17,2171.26 1340.72,2139.72 1340.72,1970.4 1338.91,1968.59 1338.91,1883.62 1340.72,1881.82 1339.2,1880.3 1339.2,1825.43 1326,1812.22 1326,1792.59 1324.67,1791.26 U4.@1324.67,1754.12 ; v1(1044.41,2326.77) 1008.98,2291.34
  Signal Layer 2 w6: v1(1044.41,2326.77) 1080.13,2291.06 1080.13,2154.93 v1(1066.93,2141.73)
  Bottom Layer w6: v1(1066.93,2141.73) 1151.57,2226.38 1151.57,2607.93 1133.86,2625.65 TP1.1@1133.86,2645.67
PROG: JP1.1 JP2.1 JP3.1 U1.20 | length 1073.5
  Top Layer w6: U1.20@878.07,2206.59 894.84,2206.59 901.33,2213.09 901.33,2243.42 910.38,2252.47 v1(910.38,2254.11)
  Bottom Layer w10: v1(910.38,2254.11) 874.02,2290.47 874.02,2712.8 JP1.1@1062.99,2901.77 JP2.1@1193.9,2901.77 JP3.1@1324.8,2901.77
REGN: C18.1 R3.2 R4.2 U1.5 | length 752.8
  Top Layer w10: U1.5@1027.68,2206.59 1049.34,2206.59 1075,2232.25 1075,2276.65 1088.7,2290.35 C18.1@1089.68,2290.35 1089.68,2412.28 v1(1086.61,2415.35)
  Signal Layer 2 w10: v1(710.63,2395.67) 712.6,2395.67 732.28,2415.35 v1(1086.61,2415.35)
  Bottom Layer w10: R4.2@708.71,2355.32 R4.2@708.71,2354.33 ; v1(710.63,2395.67) 710.63,2360.18 712.6,2358.22 R4.2@708.71,2354.33 ; R3.2@769.8,2320.87 743.23,2320.87 723.46,2340.63 722.41,2340.63 R4.2@708.71,2354.33
STAT: D1.2 U1.1 | length 1022.6
  Top Layer w10: 1032.66,2141.67 1034.58,2139.75 v1(1034.58,2122.08) ; v1(1467.87,2666.69) 1492.76,2666.69 D1.2@1496.06,2663.39
  Signal Layer 2 w10: v1(1034.58,2122.08) 1036.5,2120.17 1043.57,2120.17 1043.66,2120.08 1446.26,2120.08 1467.87,2141.68 v1@1467.87,2671.26
SYS: C12.1 C13.1 C14.1 C15.1 C16.1 C17.1 C29.1 C30.1 C31.1 J1.1 R13.2 U1.25 U3.2 | length 1655.4
  Top Layer w10: J1.1@169.29,2229.92 203.66,2195.55 203.66,2188.07 322.83,2068.9 380.02,2068.9 380.37,2068.54 497.17,2068.54 511.34,2068.54 541.34,2068.54 v1@577.87,2068.54 ; 568.9,1537.4 C29.1@622.05,1537.4 ; v1@571.34,2068.54 v1@577.87,2068.54 ; U3.2@606.69,1262.52 606.69,1321.78 C31.1@622.22,1337.3 622.05,1337.47 C30.1@622.05,1438.98 ; C30.1@618.11,1442.91 C30.1@622.05,1438.98 ; C29.1@622.05,1562.99 C29.1@622.05,1537.4 ; U1.25@917.44,2139.66 916.54,2138.76 916.54,2116.22 892.76,2092.44 882.01,2081.69 831.18,2081.69 818.03,2068.54 737.32,2068.54 657.6,2068.54 v1@577.87,2068.54 ; C30.1@622.05,1438.98 C29.1@622.05,1537.4
  Bottom Layer w10: 511.94,1577.26 v1@511.94,1598.9 ; v1(517.72,1598.9) 543.31,1624.49 543.31,1927.34 ; R13.2@525.59,1382.87 526.57,1383.86 568.9,1383.86 v1(580.71,1372.05)
  other v1: 487.72,1538.9 517.72,1538.9 547.72,1538.9 487.72,1568.9 517.72,1568.9 547.72,1568.9 487.72,1598.9 547.72,1598.9 511.34,2042.83 541.34,2042.83 571.34,2042.83 846.46,2043.31 511.34,2072.83 541.34,2072.83 571.34,2072.83 614.17,2102.36 693.66,2102.45 511.34,2102.83 541.34,2102.83 571.34,2102.83 773.39,2103.73
TS: J4.1 JP4.1 R3.1 R5.2 U1.16 | length 1096.9
  Top Layer w10: v1(849.53,2320.87) 849.53,2318.16 861.34,2306.35 861.34,2277.38 869.03,2269.69 879.98,2269.69
  Bottom Layer w10: J4.1@708.66,3027.56 847.24,3027.56 JP4.1@874.02,3000.79 938.19,3000.79 966.54,2972.44 966.54,2877.95 817.05,2728.46 R5.2@817.05,2361.22 R3.1@817.05,2320.87 v1(849.53,2320.87)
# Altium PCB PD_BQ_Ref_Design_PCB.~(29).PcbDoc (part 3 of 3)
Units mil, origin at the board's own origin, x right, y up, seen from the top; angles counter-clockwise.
Board outline 2000 x 3400 mil, 4 copper layers (Top Layer, Signal Layer 1, Signal Layer 2, Bottom Layer), stack 61.2 mil thick; 124 components, 53 nets, 359 pads, 494 vias.
Unrouted connection lines stored in the file: 227.

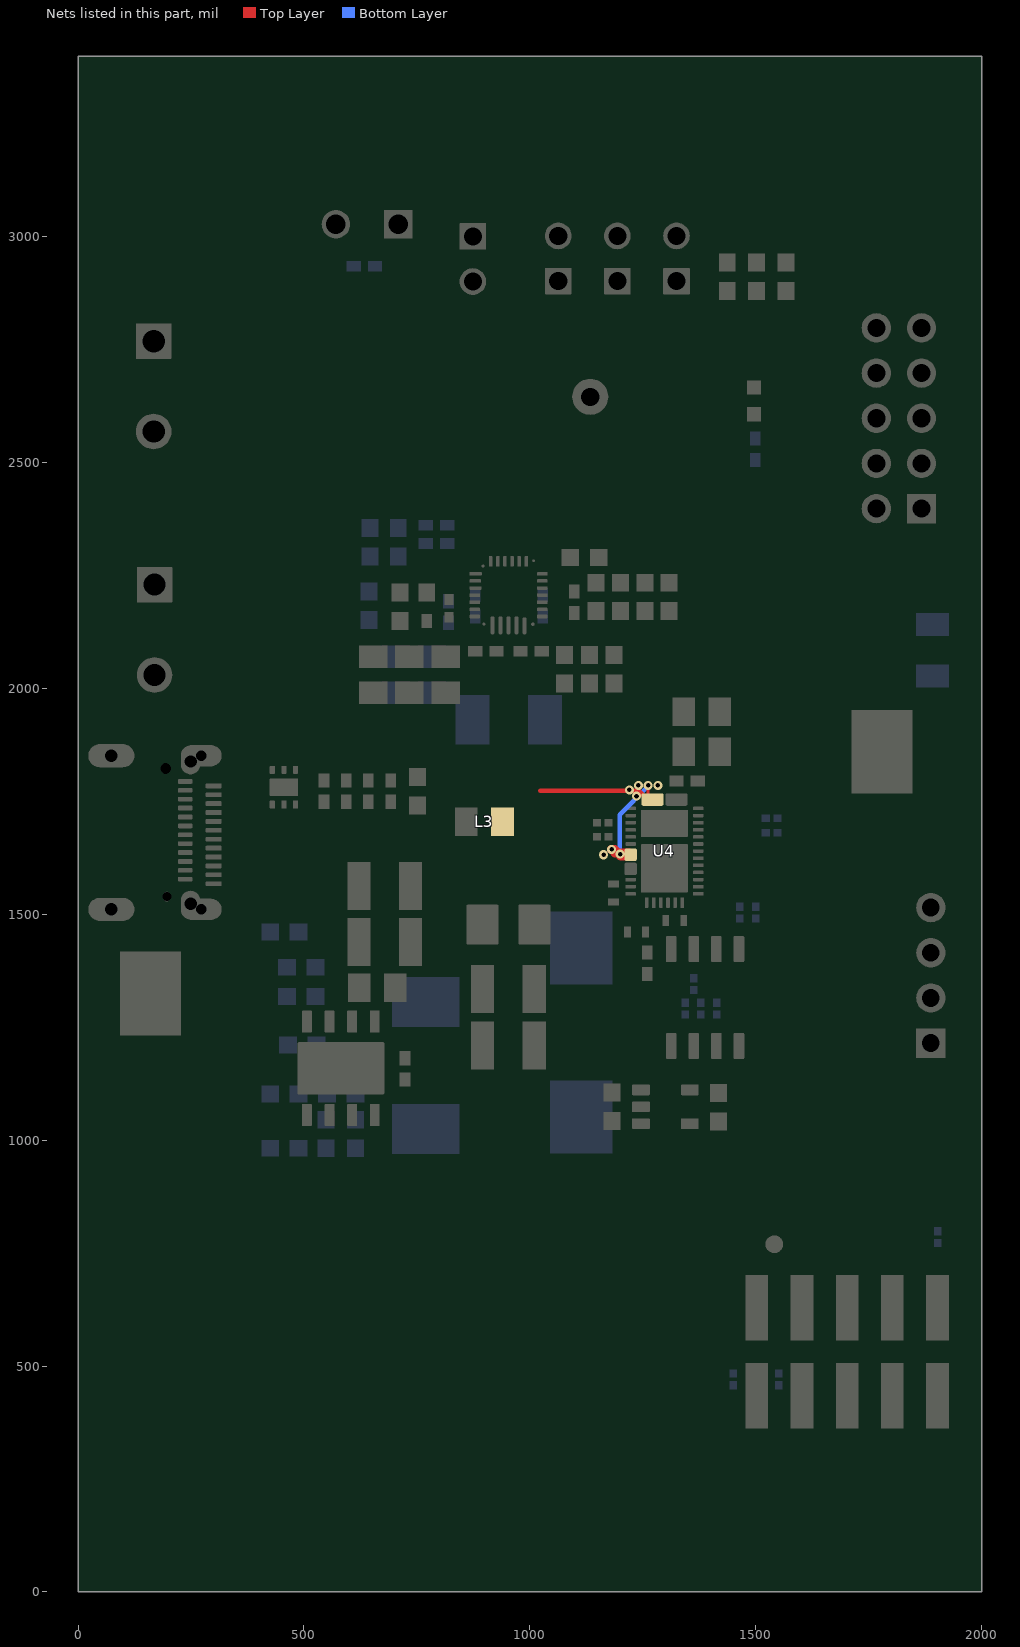
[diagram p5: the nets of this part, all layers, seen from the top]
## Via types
v1: diameter 20, hole 10, Top Layer to Bottom Layer, tented both sides, 445 vias
v2: diameter 23.62, hole 11.81, Top Layer to Bottom Layer, 24 vias
v3: diameter 30, hole 15, Top Layer to Bottom Layer, tented both sides, 12 vias
v4: diameter 19.68, hole 7.87, Top Layer to Bottom Layer, tented both sides, 10 vias
v5: diameter 20, hole 10, Top Layer to Bottom Layer, 3 vias

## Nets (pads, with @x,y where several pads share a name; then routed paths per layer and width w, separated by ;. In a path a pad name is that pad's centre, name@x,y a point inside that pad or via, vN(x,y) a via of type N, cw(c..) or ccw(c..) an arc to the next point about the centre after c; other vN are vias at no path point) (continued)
VBUS: L3.2 U4.23 U4.24 U4.25 U4.32 U4.33 U4.@1223.24,1632.07 U4.@1271.41,1754.12 | length 575.9
  Top Layer w6: v1@1198.82,1631.89 1223.06,1631.89 U4.@1223.24,1632.07 ; v1(1261.81,1785.43) 1261.81,1764.21 1271.65,1754.37 U4.@1271.41,1754.12
  Top Layer w10: 1023.62,1773.62 1220.47,1773.62 1241.02,1773.62 1260.52,1754.12 U4.@1271.41,1754.12
  Top Layer w20: v1@1208.66,1629.35 1201.35,1629.35 v1@1194.86,1635.85 ; U4.@1223.24,1632.07 1219.46,1635.85 v1@1194.86,1635.85 ; v1@1194.86,1635.85 1187.01,1643.7 v1(1181.1,1643.7) 1188.95,1635.85 v1@1194.86,1635.85
  Bottom Layer w10: v1@1198.82,1631.89 1198.82,1720.47 1261.81,1783.46 v1(1261.81,1785.43)
  other v1: 1163.39,1631.89 1199.79,1633.39 1236.22,1761.81 1220.47,1775.59 1240.16,1785.43 1283.46,1785.43
pads on no net: FID1.1 FID2.1 FID3.1 FID4.1 FID5.1 FID6.1 H1.1 H2.1 H3.1 H4.1 H5.0 H6.0 H7.0 H8.0 J3.1 J3.2 J3.3 J3.4 J3.7 J3.8 J5.4 J5.5 J5.6 J5.7 J5.8 J5.9 J6.A2 J6.A3 J6.A8 J6.A10 J6.A11 J6.ALIGN1 J6.ALIGN2 J6.B2 J6.B3 J6.B8 J6.B10 J6.B11 J7.1 SH-J1.0 SH-J2.0 U1.6 U1.7 U1.12 U1.21 U2.4 U3.9@581.69,1159.17 U4.6 U4.7 U4.13 U4.19 U4.36 U4.37 U6.7@437.99,1781.5 U6.7@473.43,1781.5

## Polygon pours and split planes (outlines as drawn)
NetC22_1 on Top Layer "TOP_LAYER_NETC22_1_P111" (solid, remove dead copper, pour order 111): 902.81,2147.24 852.76,2147.24 852.36,2147.64 852.36,2118.11 903.54,2118.11 902.81,2118.85
STAT on Top Layer "TOP_LAYER_STAT_P109" (solid, remove dead copper, pour order 109): 1001.97,2147.24 1001.97,2121.46 1003.35,2120.08 1039.37,2120.08 1039.37,2147.18 1038.91,2147.64 1038.23,2146.96 1002.66,2146.96
PPHV on Top Layer "TOP_LAYER_PPHV_P107" (solid, remove dead copper, pour order 107): 1004.63,2266.22 1004.2,2266.65 1004.2,2311.02 1043.31,2331.65 1044.25,2330.71 1053.15,2330.71 1053.15,2318.9 1037.4,2303.15 1037.4,2251.97 1039.17,2250.2 1017.72,2250.2 1017.72,2263.78 1015.27,2266.22
TS on Top Layer "TOP_LAYER_TS_P105" (solid, remove dead copper, pour order 105): 856.3,2303.15 889.65,2303.15 901.57,2291.23 901.57,2266.22 867.39,2266.22 867.11,2265.95 857.47,2275.59 856.3,2275.59
NetC1_2 on Top Layer "TOP_LAYER_NETC1_2_P103" (solid, remove dead copper, pour order 103): 964.57,2204.72 964.57,2163.39 1011.81,2163.39 1011.81,2204.72
NetC7_2 on Top Layer "TOP_LAYER_NETC7_2_P101" (solid, remove dead copper, pour order 101): 897.64,2204.72 897.64,2165.35 940.94,2165.35 940.94,2204.72
BAT on Top Layer "TOP_LAYER_BAT_P099" (solid, pour order 99): 773.62,2171.26 840.55,2171.26 840.55,2157.48 838.58,2155.51 773.62,2155.51 773.62,2171.02 773.39,2171.26
GND on Top Layer "tgaTOP_LAYER_GND_P081" (solid, pour order 97): 12.12,178.31 2012.12,178.31 2012.12,3178.31 12.12,3178.31
VBUS on Top Layer "Top Layer-VBUS" (solid, pour order 95): 1102.36,1769.69 1204.72,1769.68 1234.25,1740.16 1295.28,1740.16 1295.28,1834.64 1023.62,1834.65 954.72,1765.75 909.45,1765.75 909.45,1639.76 972.44,1639.76
NetC44_1 on Top Layer "Top Layer-NetC44_1" (solid, pour order 89): 431.1,1639.76 889.76,1639.76 889.76,1683.07 889.76,1765.75 791.34,1765.75 503.94,1765.75 492.13,1753.94 419.29,1753.94 395.67,1730.32 328.74,1730.31 328.74,1622.05 413.39,1622.05
SYS on Top Layer "Top Layer-SYS" (solid, pour order 40): 545.28,1368.11 594.49,1318.9 594.49,1273.62 618.11,1273.62 649.61,1305.12 653.54,1305.12 653.54,1620.08 462.6,1620.08 462.6,1509.84 545.28,1509.84
NetC25_2 on Top Layer "Top Layer-NetC25_2" (solid, pour order 85): 690.94,1045.28 726.38,1045.28 775.59,1094.49 775.59,1149.61 690.94,1149.61
SYS on Top Layer "Top Layer-SYS 1" (solid, pour order 72): 259.84,2027.56 863.1,2027.56 904.44,2068.9 904.44,2116.14 555.12,2116.14 533.46,2137.8 301.18,2137.8 222.44,2216.54 222.44,2285.43 200.79,2285.43 116.14,2285.43 116.14,2171.26
LDO_1V5 on Top Layer "NONET_L-01_P-001" (solid, pour order 77): 1271.65,1513.78 1271.65,1537.4 1309.06,1537.4 1309.06,1474.41 1293.31,1474.41 1293.31,1492.13
AGND on Top Layer "NONET_L-01_P-001" (solid, pour order 76): 1405.51,2907.48 1602.36,2907.48 1602.36,2828.74 1405.51,2828.74
AGND on Top Layer "NONET_L-01_P-001" (solid, pour order 75): 950.79,2269.69 938.98,2269.69 938.98,2330.71 998.03,2330.71 998.03,2269.69 970.47,2269.69 970.47,2297.24 950.79,2297.24
BAT on Top Layer "Top Layer-BAT" (solid, pour order 66): 563.04,2127.91 653.54,2127.95 830.71,2127.95 858.27,2155.51 887.8,2155.51 887.8,2179.13 850.39,2179.13 830.71,2159.45 801.18,2159.45 789.37,2171.26 692.91,2171.26 525.59,2338.58 525.59,2421.26 309.59,2637.26 108.27,2637.26 108.27,2513.78 279.53,2513.78 417.32,2375.98 417.32,2273.62
PPHV on Top Layer "Top Layer-PPHV" (solid, pour order 51): 1273.62,1740.16 1350.39,1740.16 1350.39,1820.87 1381.89,1852.36 1381.89,2021.65 1381.89,2204.72 1047.24,2204.72 1047.24,2127.95 1236.22,2127.95 1273.62,2090.55
no net on Top Layer "NONET_L-01_P-001" (solid, pour order 49): 1381.89,2021.65
no net on Top Layer "NONET_L-01_P-001" (solid, pour order 48): 1381.89,2001.97
PPHV on Top Layer "NONET_L-01_P-001" (solid, pour order 14): 1094.92,2179.13 1120.35,2204.57 1328.64,2204.57 1328.81,2149.61 1016.85,2149.61 1016.85,2179.13
REGN on Top Layer "NONET_L-01_P-001" (solid, pour order 32): 1024.72,2202.76 1052.28,2202.76 1079.84,2230.32 1079.84,2242.13 1109.37,2271.65 1109.37,2309.06 1070,2309.06 1050.31,2289.37 1050.31,2220.47 1040.47,2210.63 1024.72,2210.63
PMID on Top Layer "NONET_L-01_P-001" (solid, pour order 42): 1003.07,2116.14 1236.22,2116.14 1236.22,2041.34 1030.63,2041.34 1003.07,2068.9
P3V3 on Top Layer "NONET_L-01_P-001" (solid, pour order 30): 1210.63,1549.21 1196.85,1535.43 1196.85,1519.69 1204.72,1519.68 1226.38,1541.34 1226.38,1549.21
VBUS on Top Layer "NONET_L-01_P-001" (solid, pour order 20): 1216.54,1618.11 1216.54,1645.67 1198.82,1645.67 1187.01,1657.48 1147.64,1657.48 1147.64,1618.11
LDO_1V5 on Top Layer "NONET_L-01_P-001" (solid, pour order 31): 1309.06,1464.57 1309.06,1529.53 1271.65,1529.53 1271.65,1513.78 1291.34,1513.78 1291.34,1464.57
LDO_3V3 on Top Layer "NONET_L-01_P-001" (solid, pour order 29): 1263.78,1521.65 1269.68,1515.75 1269.68,1462.6 1250,1462.6 1250,1490.16 1250,1521.65
PP5V on Top Layer "NONET_L-01_P-001" (solid, pour order 28): 1261.81,1525.59
PP5V on Top Layer "Top Layer-PP5V" (solid, pour order 17): 968.5,1135.83 1108.27,1135.83 1108.27,1551.18 1143.7,1586.61 1236.22,1586.61 1236.22,1614.17 1155.51,1614.17 1135.64,1634.04 1037.58,1634.04 1015.75,1612.2 968.5,1564.96
NetC1_2 on Bottom Layer "NONET_L-01_P-001" (solid, pour order 44): 998.03,1877.95 998.03,1982.28 1042.44,1982.28 1042.44,1877.95
NetC7_2 on Bottom Layer "NONET_L-01_P-001" (solid, pour order 43): 911.42,1877.95 911.42,1982.28 865.28,1982.28 865.28,1877.95
GND on Bottom Layer "BOTTOM_LAYER_GND_P090" (solid, remove dead copper, pour order 90): -11.74,182.93 1988.26,182.93 1988.26,3182.93 -11.74,3182.93
SYS on Bottom Layer "Top Layer-SYS 1" (solid, pour order 87): 498.03,2027.56 863.1,2027.56 904.44,2068.9 904.44,2116.14 555.12,2116.14 533.46,2137.8 498.03,2137.8
SYS on Bottom Layer "Bottom Layer-SYS" (solid, pour order 74): 608.27,1722.44 608.27,1874.02 608.27,2118.11 498.03,2118.11 498.03,1824.8 498.03,1761.81 462.6,1726.38 462.6,1509.84 572.83,1509.84 572.83,1687.01
NetC25_2 on Bottom Layer "Bottom Layer-NetC25_2" (solid, pour order 84): 690.94,966.54 958.66,966.54 1185.04,966.54 1185.04,1082.68 775.59,1082.68 775.59,1149.61 690.94,1149.61
NetU4_15 on Bottom Layer "NONET_L-01_P-001" (solid, pour order 78): 1245.87,1732.28 1245.87,1670.46 1350.08,1670.46 1350.4,1732.28
no net on Bottom Layer "NONET_L-01_P-001" (solid, pour order 37): 537.4,2212.6
PP5V on Bottom Layer "NONET_L-01_P-001" (solid, pour order 22): 968.5,1505.91 968.5,1287.4 1183.07,1287.4 1183.07,1505.91
VBUS on Bottom Layer "NONET_L-01_P-001" (solid, pour order 21): 1210.63,1618.11 1155.51,1618.11 1155.51,1732.28 1220.47,1797.24 1295.28,1797.24 1295.28,1740.16 1236.22,1740.16 1210.63,1714.57
AGND on Signal Layer 2 "SIGNAL_LAYER_2_AGND_P083" (solid, remove dead copper, pour order 83): 3.94,171.26 2003.94,171.26 2003.94,3171.26 3.94,3171.26
NetU4_15 on Signal Layer 2 "NONET_L-01_P-001" (solid, pour order 80): 1246.06,1730.92 1246.06,1671.26 1350.27,1671.44 1350.39,1730.92
NetC7_2 on Signal Layer 2 "NONET_L-01_P-001" (solid, pour order 45): 898.74,2059.06 871.18,2059.06 871.18,2090.55 898.74,2118.11 898.74,2194.88 940.08,2194.88 940.08,2102.36
NetC1_2 on Signal Layer 2 "NONET_L-01_P-001" (solid, pour order 46): 1008.98,2059.06 1036.54,2059.06 1036.54,2090.55 1008.98,2118.11 1008.98,2194.88 967.64,2194.88 967.64,2102.36
GND on Signal Layer 1 "SIGNAL_LAYER_1_GND_P082" (solid, pour order 82): 3.94,171.26 2003.94,171.26 2003.94,3171.26 3.94,3171.26
NetU4_15 on Signal Layer 1 "NONET_L-01_P-001" (solid, pour order 79): 1246.06,1732.28 1350.39,1732.28 1350.01,1731.9 1350.01,1671.44 1246.07,1671.44

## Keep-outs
Keep-Out Layer:
  text ".Layer_Name" at 580.94,-687.23 h60

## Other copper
Top Layer:
  pour cut-out: 1003.94,1870.08 1003.94,1990.16 903.54,1990.16 903.54,1870.08
  text ".Layer_Name" at 580.94,-687.23 h60
Signal Layer 1:
  pour cut-out: 858.27,1992.13 1049.21,1992.13 1049.21,1870.08 860.24,1870.08
Signal Layer 2:
  pour cut-out: 858.27,2029.53 1049.21,2029.53 1049.21,1868.11 860.24,1868.11
Bottom Layer:
  pour cut-out: 858.27,1994.09 858.27,1868.11 1049.21,1868.11 1049.21,1994.09
  text ".Layer_Name" at 580.94,-687.23 h60

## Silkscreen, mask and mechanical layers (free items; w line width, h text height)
Top Overlay:
  lines w5: 390.75,1836.61 390.75,1944.88 390.75,2389.76 1241.14,2389.76 1496.06,2389.76 1496.06,937.01 390.75,937.01 390.75,1116.14 390.75,1839.57 ; 834.65,1866.14 850.39,1881.89 864.17,1895.67 864.17,2037.4 877.95,2051.18 ; 1031.5,2051.18 1041.34,2041.34 1041.34,1895.67 1066.93,1870.08 1073.82,1863.19 ; 1118.11,2135.83 1131.89,2122.05 1246.06,2122.05 ; 1187.01,2269.69 1208.66,2291.34 ; 1218.5,2269.69 1242.13,2293.31 ; 1265.75,2269.69 1291.34,2295.28 ; 1318.9,2271.65 1344.49,2297.24 ; 1208.66,2291.34 1208.66,2291.34
  text "'.PRJ_Number'.PCB_Rev" at 1425.2,3053.15 h108.27
  text "up to 5A" at 49.21,2891.73 h60
  text "EXT_TS" at 546.37,2818.78 h60
  text "2S" at 1045.65,2801.32 h60
  text "4S" at 1310.15,2800.31 h60
  text "3S" at 1177.55,2799.72 h60
  text "TS" at 853.46,2794.4 h60
  text "GND" at 430.01,2699.91 h60 r90
  text "STAT" at 1300.31,2658.57 h60
  text "PPHV" at 1062.12,2485.35 h60
  text "BATT" at 441.82,2467.63 h60 r90
  text "up to 10A" at 57.09,2356.48 h60
  text "SYS" at 445.76,2182.2 h60 r90
  text "USB2ANY" at 1693.02,2079.83 h60
  text "Connector" at 1626.09,2025.7 h60
  text "GND" at 443.79,1975.5 h60 r90
  text "GND" at 1749.13,1634.95 h60
  text "GND" at 83.77,1098.54 h60
  text "Aardvark" at 1659.56,797.35 h60
  text "Connector" at 1626.09,737.32 h60
  text "Total Solution Size" at 395.78,719.6 h60
  text "USB-PD-CHG-EVM-01" at 361.94,500 h108
  text ".Layer_Name" at 580.94,-687.23 h60
Bottom Overlay:
  text ".Layer_Name" at 580.94,-687.23 h60
Top Paste:
  text ".Layer_Name" at 580.94,-687.23 h60
Bottom Paste:
  text ".Layer_Name" at 580.94,-687.23 h60
Top Solder:
  text ".Layer_Name" at 580.94,-687.23 h60
  text ".Layer_Name" at 580.94,-687.23 h60
Bottom Solder:
  text ".Layer_Name" at 580.94,-687.23 h60
Drill Guide:
  text ".Layer_Name" at 580.94,-687.23 h60
M1 Board Outline:
  lines w10: 3.94,171.26 3.94,3171.26 2003.94,3171.26 2003.94,171.26 3.94,171.26
  text ".Layer_Name" at 580.94,-687.23 h60
M2 Board Dimensions:
  rectangle: 3.94,-103.74 128.94,21.26
  rectangle: 128.94,-228.74 503.94,-103.74
  lines w7: 3.94,-103.74 1003.94,-103.74 ; 128.94,-228.74 128.94,21.26 ; 253.94,-228.74 253.94,21.26 ; 503.94,-228.74 503.94,21.26 ; 753.94,-228.74 753.94,21.26 ; 3.94,-228.74 1003.94,-228.74 1003.94,21.26 3.94,21.26 3.94,-228.74
  text ".Layer_Name" at 580.94,-687.23 h60
M3 3D STEP Top:
  text ".Layer_Name" at 580.94,-687.23 h60
M4 3D STEP Bottom:
  text ".Layer_Name" at 580.94,-687.23 h60
M5 Assembly Top:
  lines w10: -288.06,-758.91 6311.94,-758.91 ; -288.06,-555.57 6313.94,-555.57 ; -288.06,-352.24 -288.06,-962.24 3716.94,-962.24 6313.94,-962.24 6313.94,-352.24 -287.56,-352.24 -287.56,-962.24 1287.94,-962.24 ; 2176.94,-962.24 2176.94,-352.24 ; 3443.94,-555.57 3443.94,-352.24 ; 4283.94,-555.57 4283.94,-352.24 ; 4905.94,-968.74 4905.94,-765.91
  text "COMPONENTS MARKED 'DNP' SHOULD NOT BE POPULATED." at 1157.44,-147.24 h60
  text "ASSEMBLY VARIANT:" at 1156.94,-262.74 h60
  text ".VariantName" at 2192.94,-262.74 h60
  text "PCB VIEWED FROM TOP SIDE" at -224.56,-484.41 h60
  text "BOARD #:" at 2251.94,-484.41 h60
  text ".PRJ_Number" at 2797.44,-484.41 h60
  text "REV:" at 3641.94,-484.41 h60
  text ".PCB_Rev" at 3933.44,-484.41 h60
  text "SVN REV:" at 4479.94,-484.41 h60
  text ".VersionControl_RevNumber" at 4985.94,-484.41 h60
  text "TID #:" at 2251.94,-687.74 h60
  text ".TID" at 2797.44,-687.74 h60
  text "PLOT NAME =" at -224.56,-893.08 h60
  text ".plot_File_Name" at 580.94,-893.08 h60
  text "GENERATED    :" at 2253.94,-893.08 h60
  text ".Print_Date" at 3123.44,-893.08 h60
  text ".Print_Time" at 3852.44,-893.08 h60
  text "TEXAS INSTRUMENTS" at 5116.94,-893.08 h60
M6 Assembly Bottom:
  lines w10: -288.56,-556.07 6313.44,-556.07 ; -286.56,-759.41 6313.44,-759.41 ; 1119.44,-969.24 1119.44,-766.41 ; 1741.44,-556.07 1741.44,-352.74 ; 2581.44,-556.07 2581.44,-352.74 ; 3848.44,-962.74 3848.44,-352.74 ; 4737.44,-962.74 6312.94,-962.74 6312.94,-352.74 -288.56,-352.74 -288.56,-962.74 2308.44,-962.74 6313.44,-962.74 6313.44,-352.74
  text "COMPONENTS MARKED 'DNP' SHOULD NOT BE POPULATED." at 6105.94,-146.74 h60
  text ".VariantName" at 5061.94,-262.74 h60
  text "ASSEMBLY VARIANT:" at 6100.94,-262.74 h60
  text ".VersionControl_RevNumber" at 1039.44,-484.91 h60
  text "SVN REV:" at 1545.44,-484.91 h60
  text ".PCB_Rev" at 2091.94,-484.91 h60
  text "REV:" at 2383.44,-484.91 h60
  text ".PRJ_Number" at 3227.94,-484.91 h60
  text "BOARD #:" at 3773.44,-484.91 h60
  text "PCB VIEWED FROM BOTTOM SIDE" at 6249.94,-484.91 h60
  text ".TID" at 3227.94,-688.24 h60
  text "TID #:" at 3773.44,-688.24 h60
  text "TEXAS INSTRUMENTS" at 908.44,-893.58 h60
  text ".Print_Time" at 2172.94,-893.58 h60
  text ".Print_Date" at 2901.94,-893.58 h60
  text "GENERATED    :" at 3771.44,-893.58 h60
  text ".plot_File_Name" at 5444.44,-893.58 h60
  text "PLOT NAME =" at 6249.94,-893.58 h60
M9 Title Sheet:
  drawing of 57 lines, arcs and shapes, not listed
  text "1" at 743.77,8207.76 h70
  text "2" at 3239.44,8207.76 h70
  text "3" at 5728.78,8207.76 h70
  text "4" at 8235.45,8207.76 h70
  text "5" at 10734.44,8207.76 h70
  text "6" at 13239.44,8207.76 h70
  text "A" at -412.56,7064.76 h70
  text "A" at 14387.44,7064.76 h70
  text "B" at -412.56,4684.76 h70
  text "B" at 14387.44,4684.76 h70
  text "C" at -412.56,2309.76 h70
  text "C" at 14387.44,2309.76 h70
  text "PROJECT TITLE:" at 11347.44,448.76 h45
  text ".PRJ_Title" at 11397.44,315.43 h70
  text "DESIGNED FOR:" at 11347.44,147.76 h45
  text ".PRJ_Customer" at 11397.44,7.76 h70
  text "D" at -412.56,-60.24 h70
  text "D" at 14387.44,-60.24 h70
  text "FILE NAME:" at 11347.44,-152.24 h45
  text ".PCB_File_Name_No_Path" at 11397.44,-272.24 h70
  text "Texas Instruments (TI) and/or its licensors do not warrant the accuracy or completeness of this specification" at 6377.94,-434.08 h45
  text "ENGINEER:" at 11347.44,-442.24 h45
  text "LAYOUT BY:" at 12852.44,-442.24 h45
  text "or any information contained therein. TI and/or its licensors do not warrant that this design will meet" at 6332.95,-546.74 h45
  text ".PRJ_Engineer" at 11397.44,-597.23 h70
  text ".PCB_Layout" at 12902.94,-597.23 h70
  text "the specifications, will be suitable for your application or fit for any particular purpose, or will operate in" at 6332.95,-659.41 h45
  text ".Layer_Name" at 580.94,-687.23 h60
  text "ALTIUM DESIGNER VERSION:" at 12852.44,-752.24 h45
  text "an implementation. TI and/or its licensors do not warrant that the design is production worthy. You should" at 6332.95,-772.07 h45
  text "completely validate and test your design implementation to confirm the system functionality for your application." at 6377.94,-884.74 h45
  text ".print_Scale" at 11397.44,-885.57 h70
  text ".Application_BuildNumber" at 12902.94,-885.57 h70
  text "1" at 743.77,-1092.24 h70
  text "2" at 3239.44,-1092.24 h70
  text "3" at 5728.78,-1092.24 h70
  text "4" at 8235.45,-1092.24 h70
  text "5" at 10734.44,-1092.24 h70
  text "6" at 13239.44,-1092.24 h70
M10 Fab Notes:
  drawing of 189 lines, arcs and shapes, not listed
  text "DESIGN INFORMATION" at 12385.96,6527.43 h60
  text "MIN. TRACK WIDTH:" at 11741.4,6395.31 h60
  text "8" at 12837.64,6395.31 h60
  text "MIL" at 12992.4,6395.31 h60
  text "MIN. CLEARANCE:" at 11741.4,6271.18 h60
  text "0.2" at 12777.64,6271.19 h60
  text "mm" at 12992.4,6271.18 h60
  text "MIN. VIA PAD SIZE:" at 11741.4,6147.06 h60
  text "24" at 12807.65,6147.06 h60
  text "MIL" at 12992.4,6147.06 h60
  text "0.05mm (2MIL)" at 12436.4,6017.16 h60
  text "MINIMUM ANNULAR RING" at 11412.16,6008.93 h60
  text "EXTERNAL" at 13144.4,6008.93 h60
  text "PER" at 11612.16,5898.81 h60
  text "IPC-D-275 CLASS 2 LEVEL C" at 11832.16,5898.8 h60
  text "MIL, HOLES" at 13320.4,5798.33 h60
  text "+/-" at 12927.94,5789.74 h60
  text "+/-" at 13781.94,5789.74 h60
  text "REGISTRATION TOLERANCES:" at 11412.16,5788.68 h60
  text "METAL" at 12611.94,5788.68 h60
  text "5" at 13188.14,5788.68 h60
  text "3" at 14021.14,5788.68 h60
  text "MIL" at 14137.4,5788.68 h60
  text "HOLE SIZE TOLERANCE (UNLESS OTHERWISE SPECIFIED):" at 11412.16,5690.36 h60
  text "+/-" at 13781.94,5687.49 h60
  text "3" at 14021.14,5686.43 h60
  text "MIL" at 14137.4,5686.43 h60
  text "MATERIAL:" at 11337.4,5548.78 h60
  text "FR-4 High Tg" at 12323.84,5420.26 h60
  text "X" at 12179.4,5412.27 h60
  text "FR-408" at 11758.4,5407.75 h60
  text "OTHER" at 13246.4,5407.75 h60
  text "62 MIL (1.6mm) +/-10%" at 12078.5,5264.72 h60
  text "X" at 11958.4,5262.27 h60
  text "THICKNESS:" at 11412.16,5256.5 h60
  text "OTHER" at 13363.4,5256.5 h60
  text "TOLERANCE:" at 11412.16,5118.18 h60
  text "X" at 12260.4,5118.18 h60
  text "ANSI IPC-6012 TYPE 3 CLASS 2" at 12438.41,5118.18 h60
  text "OTHER +/-" at 12438.4,4973.99 h60
  text "BOW & TWIST:" at 11412.16,4828.8 h60
  text "X" at 12260.4,4828.8 h60
  text "ANSI IPC-6012 TYPE 3 CLASS 2" at 12438.41,4828.8 h60
  text "OTHER +/-" at 12438.4,4682.11 h60
  text "DRILLING:" at 11337.4,4551.49 h60
  text "NC_DRILL FILES" at 13098.4,4446.3 h60
  text "REFERENCE:" at 11412.16,4442.36 h60
  text "X" at 12069.4,4442.27 h60
  text "AS SHOWN" at 12247.4,4442.36 h60
  text "X" at 12970.4,4442.36 h60
  text "OTHER" at 13396.4,4300.11 h60
  text "PTH COPPER THICKNESS:" at 11411.84,4296.58 h60
  text "X" at 12551.08,4296.58 h60
  text "20-30 um" at 12679.07,4296.58 h60
  text "BOARD FINISH:" at 11337.4,4148.99 h60
  text "SILKSCREEN:" at 11492.62,4038.86 h60
  text "X" at 12450.4,4038.86 h60
  text "TOP" at 12567.4,4038.86 h60
  text "X" at 12960.4,4038.86 h60
  text "BOTTOM" at 13078.4,4038.86 h60
  text "SILKSCREEN COLOR:" at 11492.62,3883.67 h60
  text "X" at 12449.4,3883.67 h60
  text "WHITE" at 12567.4,3883.67 h60
  text "OTHER" at 13078.4,3883.67 h60
  text "X" at 12580.4,3740.22 h60
  text "GREEN" at 12698.4,3740.22 h60
  text "OTHER" at 13316.4,3740.22 h60
  text "SOLDER RESIST COLOR:" at 11492.62,3733.36 h60
  text "X" at 12580.4,3585.97 h60
  text "MATTE" at 12698.4,3585.97 h60
  text "SEMI-GLOSS" at 13315.94,3585.33 h60
  text "IMMERSION GOLD (ENIG)" at 12398.4,3413.2 h60
  text "ENEPIG" at 13735.94,3405.98 h60
  text "SURFACE FINISH:" at 11337.4,3404.98 h60
  text "X" at 12220.4,3404.98 h60
  text "IMM. TIN/SILVER OR EQUIV" at 11666.94,3267.66 h60
  text "OTHER" at 13098.4,3263.73 h60
  text "ARRAY/PANEL:" at 11337.4,3108.35 h60
  text "CUT AND TRIM PER M1 BOARD OUTLINE" at 12398.4,3100.13 h60
  text "N.C. ROUTE" at 12398.4,2964.16 h60
  text "X" at 13086.4,2964.16 h60
  text "V. SCORE" at 13264.4,2964.16 h60
  text "CERTIFICATION:" at 11337.4,2835.03 h60
  text "MATERIALS AND WORKMANSHIP FOR ALL PCBS" at 12062.4,2835.03 h60
  text "TO MEET OR EXCEED THE REQUIREMENTS OF:" at 12062.4,2740.97 h60
  text "X" at 11699.91,2612.34 h60
  text "ANSI IPC-A-600F CLASS ->" at 11827.9,2612.34 h60
  text "X" at 13475.91,2612.34 h60
  text "2" at 13585.9,2612.34 h60
  text "1" at 13270.9,2610.84 h60
  text "3" at 13939.9,2610.84 h60
  text "X" at 12511.91,2464.65 h60
  text "RoHS" at 12639.9,2464.65 h60
  text "OTHER" at 13284.3,2464.65 h60
  text "PER ORDER" at 13681.36,2464.65 h60
  text "ALL BOARDS MUST MEET OR EXCEED UL94-V0 REQUIREMENTS." at 11364.94,2310.83 h60
  text "PCB MUST BEAR THE UL94V-0 UL REGISTERED MATERIAL ID NUMBER" at 11364.94,2194.76 h60
  text "ADDITIONAL REQUIREMENTS:" at 11337.4,2025.34 h60
  text "MICROSECTION:" at 11412.16,1918.21 h60
  text "YES" at 12317.9,1918.21 h60
  text "REQUIRED" at 13179.4,1773.88 h60
  text "BARE BOARD ELEC. TEST:" at 11412.16,1771.02 h60
  text "NONE" at 12717.9,1771.02 h60
  text "X" at 13061.4,1771.02 h60
  text "PER ORDER" at 13771.4,1771.02 h60
  text "XX MIL VIAS REQUIRE NON-CONDUCTIVE FILL AND PLANARIZE" at 11580.31,1566.08 h59
  text "XX MIL VIAS REQUIRE CONDUCTIVE FILL AND PLANARIZE" at 11588.31,1462.1 h60
  text "OUTER XX MIL TRACES REQUIRE 50 OHM SINGLE-ENDED IMPEDANCE" at 11587.33,1298.72 h58
  text "LAYER 2 & 3 (INNER LAYERS) XX MIL WIDE, XX MIL SPACE / TRACES REQUIRE 100 OHM DIFFERENTIAL IMPEDANCE" at 11579.33,1063 h60
  text ".Layer_Name" at 580.94,-687.23 h60
M11 Gerber Information:
  lines w10: -288.06,-758.91 6311.94,-758.91 ; -288.06,-555.57 6313.94,-555.57 ; -288.06,-352.24 -288.06,-962.24 3716.94,-962.24 6313.94,-962.24 6313.94,-352.24 -287.56,-352.24 -287.56,-962.24 1287.94,-962.24 ; 2176.94,-962.24 2176.94,-352.24 ; 3443.94,-555.57 3443.94,-352.24 ; 4283.94,-555.57 4283.94,-352.24 ; 4905.94,-968.74 4905.94,-765.91
  text "ALL ARTWORK VIEWED FROM TOP SIDE" at -224.56,-484.41 h60
  text "BOARD #:" at 2251.94,-484.41 h60
  text ".PRJ_Number" at 2797.44,-484.41 h60
  text "REV:" at 3641.94,-484.41 h60
  text ".PCB_Rev" at 3933.44,-484.41 h60
  text "SVN REV:" at 4479.94,-484.41 h60
  text ".VersionControl_RevNumber" at 4985.94,-484.41 h60
  text "LAYER NAME =" at -224.56,-687.23 h60
  text "TID #:" at 2251.94,-687.74 h60
  text ".TID" at 2797.44,-687.74 h60
  text "PLOT NAME =" at -224.56,-893.08 h60
  text ".plot_File_Name" at 580.94,-893.08 h60
  text "GENERATED    :" at 2253.94,-893.08 h60
  text ".Print_Date" at 3123.44,-893.08 h60
  text ".Print_Time" at 3852.44,-893.08 h60
  text "TEXAS INSTRUMENTS" at 5116.94,-893.08 h60
M12 Stackup:
  drawing of 295 lines, arcs and shapes, not listed
  text "Layer" at 9815.53,7798.7 h60
  text "Name" at 10225.44,7798.7 h60
  text "Material" at 11165.19,7798.7 h60
  text "Thickness" at 12024.95,7798.7 h60
  text "Constant" at 12674.79,7798.7 h60
  text "Board Layer Stack" at 13244.65,7798.7 h60
  text "1" at 9815.53,7678.7 h60
  text "Top Overlay" at 10225.44,7678.7 h60
  text "2" at 9815.53,7558.7 h60
  text "Top Solder" at 10225.44,7558.7 h60
  text "Solder Resist" at 11165.19,7558.7 h60
  text "0.40mil" at 12024.95,7558.7 h60
  text "3.5" at 12674.79,7558.7 h60
  text "3" at 9815.53,7438.7 h60
  text "Top Layer" at 10225.44,7438.7 h60
  text "Copper" at 11165.19,7438.7 h60
  text "2.80mil" at 12024.95,7438.7 h60
  text "4" at 9815.53,7318.7 h60
  text "Dielectric 1" at 10225.44,7318.7 h60
  text "FR-4 High TG" at 11165.19,7318.7 h60
  text "12.00mil" at 12024.95,7318.7 h60
  text "4.2" at 12674.79,7318.7 h60
  text "5" at 9815.53,7198.7 h60
  text "Signal Layer 1" at 10225.44,7198.7 h60
  text "Copper" at 11165.19,7198.7 h60
  text "2.80mil" at 12024.95,7198.7 h60
  text "6" at 9815.53,7078.7 h60
  text "Dielectric2" at 10225.44,7078.7 h60
  text "FR-4 High TG" at 11165.19,7078.7 h60
  text "26.00mil" at 12024.95,7078.7 h60
  text "4.2" at 12674.79,7078.7 h60
  text "7" at 9815.53,6958.7 h60
  text "Signal Layer 2" at 10225.44,6958.7 h60
  text "Copper" at 11165.19,6958.7 h60
  text "2.80mil" at 12024.95,6958.7 h60
  text "8" at 9815.53,6838.7 h60
  text "Dielectric3" at 10225.44,6838.7 h60
  text "FR-4 High TG" at 11165.19,6838.7 h60
  text "12.00mil" at 12024.95,6838.7 h60
  text "4.2" at 12674.79,6838.7 h60
  text "9" at 9815.53,6718.7 h60
  text "Bottom Layer" at 10225.44,6718.7 h60
  text "Copper" at 11165.19,6718.7 h60
  text "2.80mil" at 12024.95,6718.7 h60
  text "10" at 9815.53,6598.7 h60
  text "Bottom Solder" at 10225.44,6598.7 h60
  text "Solder Resist" at 11165.19,6598.7 h60
  text "0.40mil" at 12024.95,6598.7 h60
  text "3.5" at 12674.79,6598.7 h60
  text "11" at 9815.53,6478.7 h60
  text "Bottom Overlay" at 10225.44,6478.7 h60
  text ".Layer_Name" at 580.94,-687.23 h60
M13 Component Bodies Top:
  text ".Layer_Name" at 580.94,-687.23 h60
M14 Component Bodies Bottom:
  text ".Layer_Name" at 580.94,-687.23 h60
M15 Courtyards Top:
  text ".Layer_Name" at 580.94,-687.23 h60
M16 Courtyards Bottom:
  text ".Layer_Name" at 580.94,-687.23 h60
Drill Drawing:
  drawing of 152 lines, arcs and shapes, not listed
  text "Symbol" at 5364.53,3688.54 h72
  text "Quantity" at 5665.09,3688.54 h72
  text "Finished Hole Size" at 5997.1,3688.54 h72
  text "Plated" at 6633.66,3688.54 h72
  text "Hole Type" at 6892.8,3688.54 h72
  text "Drill Layer Pair" at 7267.96,3688.54 h72
  text "Hole Tolerance" at 7992.29,3688.54 h72
  text "1" at 5665.09,3564.22 h60
  text "23.62mil (0.600mm)" at 5997.1,3564.22 h60
  text "NPTH" at 6633.66,3564.22 h60
  text "Round" at 6892.8,3564.22 h60
  text "Top Layer - Bottom Layer" at 7267.96,3564.22 h60
  text "+/-1.18mil" at 7992.29,3564.22 h60
  text "10" at 5665.09,3439.9 h60
  text "7.87mil (0.200mm)" at 5997.1,3439.9 h60
  text "PTH" at 6633.66,3439.9 h60
  text "Round" at 6892.8,3439.9 h60
  text "Top Layer - Bottom Layer" at 7267.96,3439.9 h60
  text "448" at 5665.09,3315.58 h60
  text "10.00mil (0.254mm)" at 5997.1,3315.58 h60
  text "PTH" at 6633.66,3315.58 h60
  text "Round" at 6892.8,3315.58 h60
  text "Top Layer - Bottom Layer" at 7267.96,3315.58 h60
  text "24" at 5665.09,3191.26 h60
  text "11.81mil (0.300mm)" at 5997.1,3191.26 h60
  text "PTH" at 6633.66,3191.26 h60
  text "Round" at 6892.8,3191.26 h60
  text "Top Layer - Bottom Layer" at 7267.96,3191.26 h60
  text "12" at 5665.09,3066.94 h60
  text "15.00mil (0.381mm)" at 5997.1,3066.94 h60
  text "PTH" at 6633.66,3066.94 h60
  text "Round" at 6892.8,3066.94 h60
  text "Top Layer - Bottom Layer" at 7267.96,3066.94 h60
  text "4" at 5665.09,2942.62 h60
  text "39.37mil (1.000mm)" at 5997.1,2942.62 h60
  text "PTH" at 6633.66,2942.62 h60
  text "Round" at 6892.8,2942.62 h60
  text "Top Layer - Bottom Layer" at 7267.96,2942.62 h60
  text "19" at 5665.09,2818.3 h60
  text "40.00mil (1.016mm)" at 5997.1,2818.3 h60
  text "PTH" at 6633.66,2818.3 h60
  text "Round" at 6892.8,2818.3 h60
  text "Top Layer - Bottom Layer" at 7267.96,2818.3 h60
  text "2" at 5665.09,2693.98 h60
  text "43.31mil (1.100mm)" at 5997.1,2693.98 h60
  text "PTH" at 6633.66,2693.98 h60
  text "Round" at 6892.8,2693.98 h60
  text "Top Layer - Bottom Layer" at 7267.96,2693.98 h60
  text "4" at 5665.09,2569.66 h60
  text "49.21mil (1.250mm)" at 5997.1,2569.66 h60
  text "PTH" at 6633.66,2569.66 h60
  text "Round" at 6892.8,2569.66 h60
  text "Top Layer - Bottom Layer" at 7267.96,2569.66 h60
  text "4" at 5665.09,2445.34 h60
  text "125.98mil (3.200mm)" at 5997.1,2445.34 h60
  text "PTH" at 6633.66,2445.34 h60
  text "Round" at 6892.8,2445.34 h60
  text "Top Layer - Bottom Layer" at 7267.96,2445.34 h60
  text "1" at 5665.09,2321.02 h60
  text "19.69mil (0.500mm)" at 5997.1,2321.02 h60
  text "NPTH" at 6633.66,2321.02 h60
  text "Slot" at 6892.8,2321.02 h60
  text "Top Layer - Bottom Layer" at 7267.96,2321.02 h60
  text "+/-1.18mil" at 7992.29,2321.02 h60
  text "2" at 5665.09,2196.7 h60
  text "23.62mil (0.600mm)" at 5997.1,2196.7 h60
  text "PTH" at 6633.66,2196.7 h60
  text "Slot" at 6892.8,2196.7 h60
  text "Top Layer - Bottom Layer" at 7267.96,2196.7 h60
  text "+/-1.97mil" at 7992.29,2196.7 h60
  text "2" at 5665.09,2072.38 h60
  text "27.56mil (0.700mm)" at 5997.1,2072.38 h60
  text "PTH" at 6633.66,2072.38 h60
  text "Slot" at 6892.8,2072.38 h60
  text "Top Layer - Bottom Layer" at 7267.96,2072.38 h60
  text "+/-1.97mil" at 7992.29,2072.38 h60
  text "2" at 5665.09,1948.06 h60
  text "27.56mil (0.700mm)" at 5997.1,1948.06 h60
  text "PTH" at 6633.66,1948.06 h60
  text "Slot" at 6892.8,1948.06 h60
  text "Top Layer - Bottom Layer" at 7267.96,1948.06 h60
  text "+/-1.97mil" at 7992.29,1948.06 h60
  text "535 Total" at 5665.09,1823.74 h60
  text "Slot definitions :" at 5364.53,1736.71 h60
  text "Routed Path Length" at 5815.24,1736.71 h60
  text "= Calculated from tool start centre position to tool end centre position." at 6354.98,1736.71 h60
  text "Hole Length" at 5815.24,1686.99 h60
  text "= Routed Path Length + Tool Size = Slot length as defined in the PCB layout" at 6155.18,1686.99 h60
  text ".Layer_Name" at 580.94,-687.23 h60
M17 Embedded Cavity:
  text ".Layer_Name" at 580.94,-687.23 h60
M18 Embedded Assembly:
  text ".Layer_Name" at 580.94,-687.23 h60
M19 Embedded Keepout:
  text ".Layer_Name" at 580.94,-687.23 h60

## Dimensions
1496.06,2389.76 to 1496.06,937.01 on Top Overlay
390.75,937.01 to 1496.06,937.01 on Top Overlay
3.94,-228.74 to 1003.94,-228.74 on M2 Board Dimensions
3.94,171.26 to 0,3400 on M2 Board Dimensions
3.94,171.26 to 2000,0 on M2 Board Dimensions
